VERSION 5.8 ;
BUSBITCHARS "[]" ;
DIVIDERCHAR "/" ;
UNITS
    DATABASE MICRONS 1000 ;
END UNITS

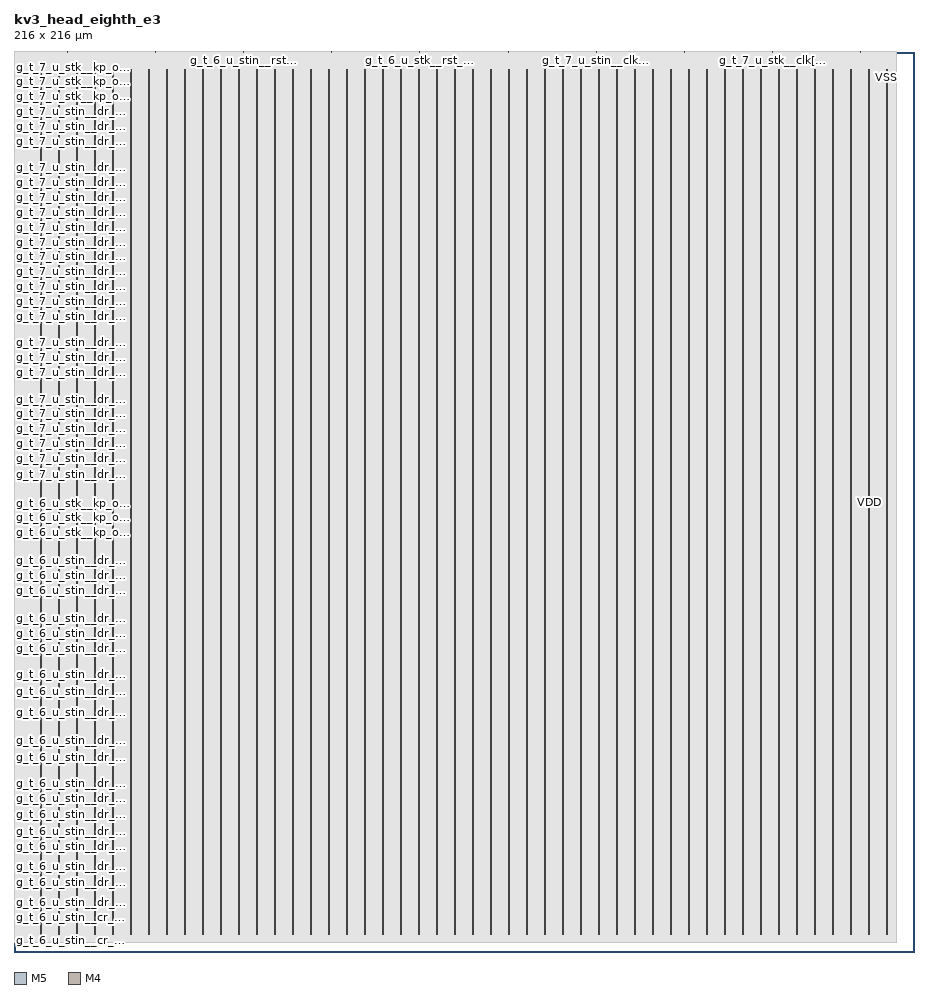
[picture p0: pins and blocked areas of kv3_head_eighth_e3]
MACRO kv3_head_eighth_e3
  FOREIGN kv3_head_eighth_e3 0 0 ;
  CLASS BLOCK ;
  SIZE 216 BY 216 ;
  PIN g_t_6_u_l8__clk[0]
    DIRECTION INPUT ;
    USE SIGNAL ;
    PORT
      LAYER M5 ;
        RECT  12.732 215.808 12.756 216 ;
    END
  END g_t_6_u_l8__clk[0]
  PIN g_t_6_u_stin__clk[0]
    DIRECTION INPUT ;
    USE SIGNAL ;
    PORT
      LAYER M5 ;
        RECT  33.9 215.808 33.924 216 ;
    END
  END g_t_6_u_stin__clk[0]
  PIN g_t_6_u_stin__cr_i[0]
    DIRECTION INPUT ;
    USE SIGNAL ;
    PORT
      LAYER M4 ;
        RECT  0 2.364 0.192 2.388 ;
    END
  END g_t_6_u_stin__cr_i[0]
  PIN g_t_6_u_stin__cr_i[10]
    DIRECTION INPUT ;
    USE SIGNAL ;
    PORT
      LAYER M4 ;
        RECT  0 6.3 0.192 6.324 ;
    END
  END g_t_6_u_stin__cr_i[10]
  PIN g_t_6_u_stin__cr_i[11]
    DIRECTION INPUT ;
    USE SIGNAL ;
    PORT
      LAYER M4 ;
        RECT  0 6.684 0.192 6.708 ;
    END
  END g_t_6_u_stin__cr_i[11]
  PIN g_t_6_u_stin__cr_i[12]
    DIRECTION INPUT ;
    USE SIGNAL ;
    PORT
      LAYER M4 ;
        RECT  0 7.116 0.192 7.14 ;
    END
  END g_t_6_u_stin__cr_i[12]
  PIN g_t_6_u_stin__cr_i[13]
    DIRECTION INPUT ;
    USE SIGNAL ;
    PORT
      LAYER M4 ;
        RECT  0 7.5 0.192 7.524 ;
    END
  END g_t_6_u_stin__cr_i[13]
  PIN g_t_6_u_stin__cr_i[14]
    DIRECTION INPUT ;
    USE SIGNAL ;
    PORT
      LAYER M4 ;
        RECT  0 7.884 0.192 7.908 ;
    END
  END g_t_6_u_stin__cr_i[14]
  PIN g_t_6_u_stin__cr_i[15]
    DIRECTION INPUT ;
    USE SIGNAL ;
    PORT
      LAYER M4 ;
        RECT  0 8.316 0.192 8.34 ;
    END
  END g_t_6_u_stin__cr_i[15]
  PIN g_t_6_u_stin__cr_i[1]
    DIRECTION INPUT ;
    USE SIGNAL ;
    PORT
      LAYER M4 ;
        RECT  0 2.748 0.192 2.772 ;
    END
  END g_t_6_u_stin__cr_i[1]
  PIN g_t_6_u_stin__cr_i[2]
    DIRECTION INPUT ;
    USE SIGNAL ;
    PORT
      LAYER M4 ;
        RECT  0 3.132 0.192 3.156 ;
    END
  END g_t_6_u_stin__cr_i[2]
  PIN g_t_6_u_stin__cr_i[3]
    DIRECTION INPUT ;
    USE SIGNAL ;
    PORT
      LAYER M4 ;
        RECT  0 3.516 0.192 3.54 ;
    END
  END g_t_6_u_stin__cr_i[3]
  PIN g_t_6_u_stin__cr_i[4]
    DIRECTION INPUT ;
    USE SIGNAL ;
    PORT
      LAYER M4 ;
        RECT  0 3.948 0.192 3.972 ;
    END
  END g_t_6_u_stin__cr_i[4]
  PIN g_t_6_u_stin__cr_i[5]
    DIRECTION INPUT ;
    USE SIGNAL ;
    PORT
      LAYER M4 ;
        RECT  0 4.332 0.192 4.356 ;
    END
  END g_t_6_u_stin__cr_i[5]
  PIN g_t_6_u_stin__cr_i[6]
    DIRECTION INPUT ;
    USE SIGNAL ;
    PORT
      LAYER M4 ;
        RECT  0 4.716 0.192 4.74 ;
    END
  END g_t_6_u_stin__cr_i[6]
  PIN g_t_6_u_stin__cr_i[7]
    DIRECTION INPUT ;
    USE SIGNAL ;
    PORT
      LAYER M4 ;
        RECT  0 5.1 0.192 5.124 ;
    END
  END g_t_6_u_stin__cr_i[7]
  PIN g_t_6_u_stin__cr_i[8]
    DIRECTION INPUT ;
    USE SIGNAL ;
    PORT
      LAYER M4 ;
        RECT  0 5.532 0.192 5.556 ;
    END
  END g_t_6_u_stin__cr_i[8]
  PIN g_t_6_u_stin__cr_i[9]
    DIRECTION INPUT ;
    USE SIGNAL ;
    PORT
      LAYER M4 ;
        RECT  0 5.916 0.192 5.94 ;
    END
  END g_t_6_u_stin__cr_i[9]
  PIN g_t_6_u_stin__dr_i[0]
    DIRECTION INPUT ;
    USE SIGNAL ;
    PORT
      LAYER M4 ;
        RECT  0 8.7 0.192 8.724 ;
    END
  END g_t_6_u_stin__dr_i[0]
  PIN g_t_6_u_stin__dr_i[100]
    DIRECTION INPUT ;
    USE SIGNAL ;
    PORT
      LAYER M4 ;
        RECT  0 48.348 0.192 48.372 ;
    END
  END g_t_6_u_stin__dr_i[100]
  PIN g_t_6_u_stin__dr_i[101]
    DIRECTION INPUT ;
    USE SIGNAL ;
    PORT
      LAYER M4 ;
        RECT  0 48.732 0.192 48.756 ;
    END
  END g_t_6_u_stin__dr_i[101]
  PIN g_t_6_u_stin__dr_i[102]
    DIRECTION INPUT ;
    USE SIGNAL ;
    PORT
      LAYER M4 ;
        RECT  0 49.116 0.192 49.14 ;
    END
  END g_t_6_u_stin__dr_i[102]
  PIN g_t_6_u_stin__dr_i[103]
    DIRECTION INPUT ;
    USE SIGNAL ;
    PORT
      LAYER M4 ;
        RECT  0 49.5 0.192 49.524 ;
    END
  END g_t_6_u_stin__dr_i[103]
  PIN g_t_6_u_stin__dr_i[104]
    DIRECTION INPUT ;
    USE SIGNAL ;
    PORT
      LAYER M4 ;
        RECT  0 49.932 0.192 49.956 ;
    END
  END g_t_6_u_stin__dr_i[104]
  PIN g_t_6_u_stin__dr_i[105]
    DIRECTION INPUT ;
    USE SIGNAL ;
    PORT
      LAYER M4 ;
        RECT  0 50.316 0.192 50.34 ;
    END
  END g_t_6_u_stin__dr_i[105]
  PIN g_t_6_u_stin__dr_i[106]
    DIRECTION INPUT ;
    USE SIGNAL ;
    PORT
      LAYER M4 ;
        RECT  0 50.7 0.192 50.724 ;
    END
  END g_t_6_u_stin__dr_i[106]
  PIN g_t_6_u_stin__dr_i[107]
    DIRECTION INPUT ;
    USE SIGNAL ;
    PORT
      LAYER M4 ;
        RECT  0 51.084 0.192 51.108 ;
    END
  END g_t_6_u_stin__dr_i[107]
  PIN g_t_6_u_stin__dr_i[108]
    DIRECTION INPUT ;
    USE SIGNAL ;
    PORT
      LAYER M4 ;
        RECT  0 51.516 0.192 51.54 ;
    END
  END g_t_6_u_stin__dr_i[108]
  PIN g_t_6_u_stin__dr_i[109]
    DIRECTION INPUT ;
    USE SIGNAL ;
    PORT
      LAYER M4 ;
        RECT  0 51.9 0.192 51.924 ;
    END
  END g_t_6_u_stin__dr_i[109]
  PIN g_t_6_u_stin__dr_i[10]
    DIRECTION INPUT ;
    USE SIGNAL ;
    PORT
      LAYER M4 ;
        RECT  0 12.636 0.192 12.66 ;
    END
  END g_t_6_u_stin__dr_i[10]
  PIN g_t_6_u_stin__dr_i[110]
    DIRECTION INPUT ;
    USE SIGNAL ;
    PORT
      LAYER M4 ;
        RECT  0 52.284 0.192 52.308 ;
    END
  END g_t_6_u_stin__dr_i[110]
  PIN g_t_6_u_stin__dr_i[111]
    DIRECTION INPUT ;
    USE SIGNAL ;
    PORT
      LAYER M4 ;
        RECT  0 52.668 0.192 52.692 ;
    END
  END g_t_6_u_stin__dr_i[111]
  PIN g_t_6_u_stin__dr_i[112]
    DIRECTION INPUT ;
    USE SIGNAL ;
    PORT
      LAYER M4 ;
        RECT  0 53.1 0.192 53.124 ;
    END
  END g_t_6_u_stin__dr_i[112]
  PIN g_t_6_u_stin__dr_i[113]
    DIRECTION INPUT ;
    USE SIGNAL ;
    PORT
      LAYER M4 ;
        RECT  0 53.484 0.192 53.508 ;
    END
  END g_t_6_u_stin__dr_i[113]
  PIN g_t_6_u_stin__dr_i[114]
    DIRECTION INPUT ;
    USE SIGNAL ;
    PORT
      LAYER M4 ;
        RECT  0 53.868 0.192 53.892 ;
    END
  END g_t_6_u_stin__dr_i[114]
  PIN g_t_6_u_stin__dr_i[115]
    DIRECTION INPUT ;
    USE SIGNAL ;
    PORT
      LAYER M4 ;
        RECT  0 54.252 0.192 54.276 ;
    END
  END g_t_6_u_stin__dr_i[115]
  PIN g_t_6_u_stin__dr_i[116]
    DIRECTION INPUT ;
    USE SIGNAL ;
    PORT
      LAYER M4 ;
        RECT  0 54.684 0.192 54.708 ;
    END
  END g_t_6_u_stin__dr_i[116]
  PIN g_t_6_u_stin__dr_i[117]
    DIRECTION INPUT ;
    USE SIGNAL ;
    PORT
      LAYER M4 ;
        RECT  0 55.068 0.192 55.092 ;
    END
  END g_t_6_u_stin__dr_i[117]
  PIN g_t_6_u_stin__dr_i[118]
    DIRECTION INPUT ;
    USE SIGNAL ;
    PORT
      LAYER M4 ;
        RECT  0 55.452 0.192 55.476 ;
    END
  END g_t_6_u_stin__dr_i[118]
  PIN g_t_6_u_stin__dr_i[119]
    DIRECTION INPUT ;
    USE SIGNAL ;
    PORT
      LAYER M4 ;
        RECT  0 55.884 0.192 55.908 ;
    END
  END g_t_6_u_stin__dr_i[119]
  PIN g_t_6_u_stin__dr_i[11]
    DIRECTION INPUT ;
    USE SIGNAL ;
    PORT
      LAYER M4 ;
        RECT  0 13.068 0.192 13.092 ;
    END
  END g_t_6_u_stin__dr_i[11]
  PIN g_t_6_u_stin__dr_i[120]
    DIRECTION INPUT ;
    USE SIGNAL ;
    PORT
      LAYER M4 ;
        RECT  0 56.268 0.192 56.292 ;
    END
  END g_t_6_u_stin__dr_i[120]
  PIN g_t_6_u_stin__dr_i[121]
    DIRECTION INPUT ;
    USE SIGNAL ;
    PORT
      LAYER M4 ;
        RECT  0 56.652 0.192 56.676 ;
    END
  END g_t_6_u_stin__dr_i[121]
  PIN g_t_6_u_stin__dr_i[122]
    DIRECTION INPUT ;
    USE SIGNAL ;
    PORT
      LAYER M4 ;
        RECT  0 57.036 0.192 57.06 ;
    END
  END g_t_6_u_stin__dr_i[122]
  PIN g_t_6_u_stin__dr_i[123]
    DIRECTION INPUT ;
    USE SIGNAL ;
    PORT
      LAYER M4 ;
        RECT  0 57.468 0.192 57.492 ;
    END
  END g_t_6_u_stin__dr_i[123]
  PIN g_t_6_u_stin__dr_i[124]
    DIRECTION INPUT ;
    USE SIGNAL ;
    PORT
      LAYER M4 ;
        RECT  0 57.852 0.192 57.876 ;
    END
  END g_t_6_u_stin__dr_i[124]
  PIN g_t_6_u_stin__dr_i[125]
    DIRECTION INPUT ;
    USE SIGNAL ;
    PORT
      LAYER M4 ;
        RECT  0 58.236 0.192 58.26 ;
    END
  END g_t_6_u_stin__dr_i[125]
  PIN g_t_6_u_stin__dr_i[126]
    DIRECTION INPUT ;
    USE SIGNAL ;
    PORT
      LAYER M4 ;
        RECT  0 58.62 0.192 58.644 ;
    END
  END g_t_6_u_stin__dr_i[126]
  PIN g_t_6_u_stin__dr_i[127]
    DIRECTION INPUT ;
    USE SIGNAL ;
    PORT
      LAYER M4 ;
        RECT  0 59.052 0.192 59.076 ;
    END
  END g_t_6_u_stin__dr_i[127]
  PIN g_t_6_u_stin__dr_i[128]
    DIRECTION INPUT ;
    USE SIGNAL ;
    PORT
      LAYER M4 ;
        RECT  0 59.436 0.192 59.46 ;
    END
  END g_t_6_u_stin__dr_i[128]
  PIN g_t_6_u_stin__dr_i[129]
    DIRECTION INPUT ;
    USE SIGNAL ;
    PORT
      LAYER M4 ;
        RECT  0 59.82 0.192 59.844 ;
    END
  END g_t_6_u_stin__dr_i[129]
  PIN g_t_6_u_stin__dr_i[12]
    DIRECTION INPUT ;
    USE SIGNAL ;
    PORT
      LAYER M4 ;
        RECT  0 13.452 0.192 13.476 ;
    END
  END g_t_6_u_stin__dr_i[12]
  PIN g_t_6_u_stin__dr_i[130]
    DIRECTION INPUT ;
    USE SIGNAL ;
    PORT
      LAYER M4 ;
        RECT  0 60.204 0.192 60.228 ;
    END
  END g_t_6_u_stin__dr_i[130]
  PIN g_t_6_u_stin__dr_i[131]
    DIRECTION INPUT ;
    USE SIGNAL ;
    PORT
      LAYER M4 ;
        RECT  0 60.636 0.192 60.66 ;
    END
  END g_t_6_u_stin__dr_i[131]
  PIN g_t_6_u_stin__dr_i[132]
    DIRECTION INPUT ;
    USE SIGNAL ;
    PORT
      LAYER M4 ;
        RECT  0 61.02 0.192 61.044 ;
    END
  END g_t_6_u_stin__dr_i[132]
  PIN g_t_6_u_stin__dr_i[133]
    DIRECTION INPUT ;
    USE SIGNAL ;
    PORT
      LAYER M4 ;
        RECT  0 61.404 0.192 61.428 ;
    END
  END g_t_6_u_stin__dr_i[133]
  PIN g_t_6_u_stin__dr_i[134]
    DIRECTION INPUT ;
    USE SIGNAL ;
    PORT
      LAYER M4 ;
        RECT  0 61.788 0.192 61.812 ;
    END
  END g_t_6_u_stin__dr_i[134]
  PIN g_t_6_u_stin__dr_i[135]
    DIRECTION INPUT ;
    USE SIGNAL ;
    PORT
      LAYER M4 ;
        RECT  0 62.22 0.192 62.244 ;
    END
  END g_t_6_u_stin__dr_i[135]
  PIN g_t_6_u_stin__dr_i[136]
    DIRECTION INPUT ;
    USE SIGNAL ;
    PORT
      LAYER M4 ;
        RECT  0 62.604 0.192 62.628 ;
    END
  END g_t_6_u_stin__dr_i[136]
  PIN g_t_6_u_stin__dr_i[137]
    DIRECTION INPUT ;
    USE SIGNAL ;
    PORT
      LAYER M4 ;
        RECT  0 62.988 0.192 63.012 ;
    END
  END g_t_6_u_stin__dr_i[137]
  PIN g_t_6_u_stin__dr_i[138]
    DIRECTION INPUT ;
    USE SIGNAL ;
    PORT
      LAYER M4 ;
        RECT  0 63.372 0.192 63.396 ;
    END
  END g_t_6_u_stin__dr_i[138]
  PIN g_t_6_u_stin__dr_i[139]
    DIRECTION INPUT ;
    USE SIGNAL ;
    PORT
      LAYER M4 ;
        RECT  0 63.804 0.192 63.828 ;
    END
  END g_t_6_u_stin__dr_i[139]
  PIN g_t_6_u_stin__dr_i[13]
    DIRECTION INPUT ;
    USE SIGNAL ;
    PORT
      LAYER M4 ;
        RECT  0 13.836 0.192 13.86 ;
    END
  END g_t_6_u_stin__dr_i[13]
  PIN g_t_6_u_stin__dr_i[140]
    DIRECTION INPUT ;
    USE SIGNAL ;
    PORT
      LAYER M4 ;
        RECT  0 64.188 0.192 64.212 ;
    END
  END g_t_6_u_stin__dr_i[140]
  PIN g_t_6_u_stin__dr_i[141]
    DIRECTION INPUT ;
    USE SIGNAL ;
    PORT
      LAYER M4 ;
        RECT  0 64.572 0.192 64.596 ;
    END
  END g_t_6_u_stin__dr_i[141]
  PIN g_t_6_u_stin__dr_i[142]
    DIRECTION INPUT ;
    USE SIGNAL ;
    PORT
      LAYER M4 ;
        RECT  0 64.956 0.192 64.98 ;
    END
  END g_t_6_u_stin__dr_i[142]
  PIN g_t_6_u_stin__dr_i[143]
    DIRECTION INPUT ;
    USE SIGNAL ;
    PORT
      LAYER M4 ;
        RECT  0 65.388 0.192 65.412 ;
    END
  END g_t_6_u_stin__dr_i[143]
  PIN g_t_6_u_stin__dr_i[144]
    DIRECTION INPUT ;
    USE SIGNAL ;
    PORT
      LAYER M4 ;
        RECT  0 65.772 0.192 65.796 ;
    END
  END g_t_6_u_stin__dr_i[144]
  PIN g_t_6_u_stin__dr_i[145]
    DIRECTION INPUT ;
    USE SIGNAL ;
    PORT
      LAYER M4 ;
        RECT  0 66.156 0.192 66.18 ;
    END
  END g_t_6_u_stin__dr_i[145]
  PIN g_t_6_u_stin__dr_i[146]
    DIRECTION INPUT ;
    USE SIGNAL ;
    PORT
      LAYER M4 ;
        RECT  0 66.54 0.192 66.564 ;
    END
  END g_t_6_u_stin__dr_i[146]
  PIN g_t_6_u_stin__dr_i[147]
    DIRECTION INPUT ;
    USE SIGNAL ;
    PORT
      LAYER M4 ;
        RECT  0 66.972 0.192 66.996 ;
    END
  END g_t_6_u_stin__dr_i[147]
  PIN g_t_6_u_stin__dr_i[148]
    DIRECTION INPUT ;
    USE SIGNAL ;
    PORT
      LAYER M4 ;
        RECT  0 67.356 0.192 67.38 ;
    END
  END g_t_6_u_stin__dr_i[148]
  PIN g_t_6_u_stin__dr_i[149]
    DIRECTION INPUT ;
    USE SIGNAL ;
    PORT
      LAYER M4 ;
        RECT  0 67.74 0.192 67.764 ;
    END
  END g_t_6_u_stin__dr_i[149]
  PIN g_t_6_u_stin__dr_i[14]
    DIRECTION INPUT ;
    USE SIGNAL ;
    PORT
      LAYER M4 ;
        RECT  0 14.22 0.192 14.244 ;
    END
  END g_t_6_u_stin__dr_i[14]
  PIN g_t_6_u_stin__dr_i[150]
    DIRECTION INPUT ;
    USE SIGNAL ;
    PORT
      LAYER M4 ;
        RECT  0 68.172 0.192 68.196 ;
    END
  END g_t_6_u_stin__dr_i[150]
  PIN g_t_6_u_stin__dr_i[151]
    DIRECTION INPUT ;
    USE SIGNAL ;
    PORT
      LAYER M4 ;
        RECT  0 68.556 0.192 68.58 ;
    END
  END g_t_6_u_stin__dr_i[151]
  PIN g_t_6_u_stin__dr_i[152]
    DIRECTION INPUT ;
    USE SIGNAL ;
    PORT
      LAYER M4 ;
        RECT  0 68.94 0.192 68.964 ;
    END
  END g_t_6_u_stin__dr_i[152]
  PIN g_t_6_u_stin__dr_i[153]
    DIRECTION INPUT ;
    USE SIGNAL ;
    PORT
      LAYER M4 ;
        RECT  0 69.324 0.192 69.348 ;
    END
  END g_t_6_u_stin__dr_i[153]
  PIN g_t_6_u_stin__dr_i[154]
    DIRECTION INPUT ;
    USE SIGNAL ;
    PORT
      LAYER M4 ;
        RECT  0 69.756 0.192 69.78 ;
    END
  END g_t_6_u_stin__dr_i[154]
  PIN g_t_6_u_stin__dr_i[155]
    DIRECTION INPUT ;
    USE SIGNAL ;
    PORT
      LAYER M4 ;
        RECT  0 70.14 0.192 70.164 ;
    END
  END g_t_6_u_stin__dr_i[155]
  PIN g_t_6_u_stin__dr_i[156]
    DIRECTION INPUT ;
    USE SIGNAL ;
    PORT
      LAYER M4 ;
        RECT  0 70.524 0.192 70.548 ;
    END
  END g_t_6_u_stin__dr_i[156]
  PIN g_t_6_u_stin__dr_i[157]
    DIRECTION INPUT ;
    USE SIGNAL ;
    PORT
      LAYER M4 ;
        RECT  0 70.908 0.192 70.932 ;
    END
  END g_t_6_u_stin__dr_i[157]
  PIN g_t_6_u_stin__dr_i[158]
    DIRECTION INPUT ;
    USE SIGNAL ;
    PORT
      LAYER M4 ;
        RECT  0 71.34 0.192 71.364 ;
    END
  END g_t_6_u_stin__dr_i[158]
  PIN g_t_6_u_stin__dr_i[159]
    DIRECTION INPUT ;
    USE SIGNAL ;
    PORT
      LAYER M4 ;
        RECT  0 71.724 0.192 71.748 ;
    END
  END g_t_6_u_stin__dr_i[159]
  PIN g_t_6_u_stin__dr_i[15]
    DIRECTION INPUT ;
    USE SIGNAL ;
    PORT
      LAYER M4 ;
        RECT  0 14.652 0.192 14.676 ;
    END
  END g_t_6_u_stin__dr_i[15]
  PIN g_t_6_u_stin__dr_i[160]
    DIRECTION INPUT ;
    USE SIGNAL ;
    PORT
      LAYER M4 ;
        RECT  0 72.108 0.192 72.132 ;
    END
  END g_t_6_u_stin__dr_i[160]
  PIN g_t_6_u_stin__dr_i[161]
    DIRECTION INPUT ;
    USE SIGNAL ;
    PORT
      LAYER M4 ;
        RECT  0 72.492 0.192 72.516 ;
    END
  END g_t_6_u_stin__dr_i[161]
  PIN g_t_6_u_stin__dr_i[162]
    DIRECTION INPUT ;
    USE SIGNAL ;
    PORT
      LAYER M4 ;
        RECT  0 72.924 0.192 72.948 ;
    END
  END g_t_6_u_stin__dr_i[162]
  PIN g_t_6_u_stin__dr_i[163]
    DIRECTION INPUT ;
    USE SIGNAL ;
    PORT
      LAYER M4 ;
        RECT  0 73.308 0.192 73.332 ;
    END
  END g_t_6_u_stin__dr_i[163]
  PIN g_t_6_u_stin__dr_i[164]
    DIRECTION INPUT ;
    USE SIGNAL ;
    PORT
      LAYER M4 ;
        RECT  0 73.692 0.192 73.716 ;
    END
  END g_t_6_u_stin__dr_i[164]
  PIN g_t_6_u_stin__dr_i[165]
    DIRECTION INPUT ;
    USE SIGNAL ;
    PORT
      LAYER M4 ;
        RECT  0 74.076 0.192 74.1 ;
    END
  END g_t_6_u_stin__dr_i[165]
  PIN g_t_6_u_stin__dr_i[166]
    DIRECTION INPUT ;
    USE SIGNAL ;
    PORT
      LAYER M4 ;
        RECT  0 74.508 0.192 74.532 ;
    END
  END g_t_6_u_stin__dr_i[166]
  PIN g_t_6_u_stin__dr_i[167]
    DIRECTION INPUT ;
    USE SIGNAL ;
    PORT
      LAYER M4 ;
        RECT  0 74.892 0.192 74.916 ;
    END
  END g_t_6_u_stin__dr_i[167]
  PIN g_t_6_u_stin__dr_i[168]
    DIRECTION INPUT ;
    USE SIGNAL ;
    PORT
      LAYER M4 ;
        RECT  0 75.276 0.192 75.3 ;
    END
  END g_t_6_u_stin__dr_i[168]
  PIN g_t_6_u_stin__dr_i[169]
    DIRECTION INPUT ;
    USE SIGNAL ;
    PORT
      LAYER M4 ;
        RECT  0 75.66 0.192 75.684 ;
    END
  END g_t_6_u_stin__dr_i[169]
  PIN g_t_6_u_stin__dr_i[16]
    DIRECTION INPUT ;
    USE SIGNAL ;
    PORT
      LAYER M4 ;
        RECT  0 15.036 0.192 15.06 ;
    END
  END g_t_6_u_stin__dr_i[16]
  PIN g_t_6_u_stin__dr_i[170]
    DIRECTION INPUT ;
    USE SIGNAL ;
    PORT
      LAYER M4 ;
        RECT  0 76.092 0.192 76.116 ;
    END
  END g_t_6_u_stin__dr_i[170]
  PIN g_t_6_u_stin__dr_i[171]
    DIRECTION INPUT ;
    USE SIGNAL ;
    PORT
      LAYER M4 ;
        RECT  0 76.476 0.192 76.5 ;
    END
  END g_t_6_u_stin__dr_i[171]
  PIN g_t_6_u_stin__dr_i[172]
    DIRECTION INPUT ;
    USE SIGNAL ;
    PORT
      LAYER M4 ;
        RECT  0 76.86 0.192 76.884 ;
    END
  END g_t_6_u_stin__dr_i[172]
  PIN g_t_6_u_stin__dr_i[173]
    DIRECTION INPUT ;
    USE SIGNAL ;
    PORT
      LAYER M4 ;
        RECT  0 77.244 0.192 77.268 ;
    END
  END g_t_6_u_stin__dr_i[173]
  PIN g_t_6_u_stin__dr_i[174]
    DIRECTION INPUT ;
    USE SIGNAL ;
    PORT
      LAYER M4 ;
        RECT  0 77.676 0.192 77.7 ;
    END
  END g_t_6_u_stin__dr_i[174]
  PIN g_t_6_u_stin__dr_i[175]
    DIRECTION INPUT ;
    USE SIGNAL ;
    PORT
      LAYER M4 ;
        RECT  0 78.06 0.192 78.084 ;
    END
  END g_t_6_u_stin__dr_i[175]
  PIN g_t_6_u_stin__dr_i[176]
    DIRECTION INPUT ;
    USE SIGNAL ;
    PORT
      LAYER M4 ;
        RECT  0 78.444 0.192 78.468 ;
    END
  END g_t_6_u_stin__dr_i[176]
  PIN g_t_6_u_stin__dr_i[177]
    DIRECTION INPUT ;
    USE SIGNAL ;
    PORT
      LAYER M4 ;
        RECT  0 78.876 0.192 78.9 ;
    END
  END g_t_6_u_stin__dr_i[177]
  PIN g_t_6_u_stin__dr_i[178]
    DIRECTION INPUT ;
    USE SIGNAL ;
    PORT
      LAYER M4 ;
        RECT  0 79.26 0.192 79.284 ;
    END
  END g_t_6_u_stin__dr_i[178]
  PIN g_t_6_u_stin__dr_i[179]
    DIRECTION INPUT ;
    USE SIGNAL ;
    PORT
      LAYER M4 ;
        RECT  0 79.644 0.192 79.668 ;
    END
  END g_t_6_u_stin__dr_i[179]
  PIN g_t_6_u_stin__dr_i[17]
    DIRECTION INPUT ;
    USE SIGNAL ;
    PORT
      LAYER M4 ;
        RECT  0 15.42 0.192 15.444 ;
    END
  END g_t_6_u_stin__dr_i[17]
  PIN g_t_6_u_stin__dr_i[180]
    DIRECTION INPUT ;
    USE SIGNAL ;
    PORT
      LAYER M4 ;
        RECT  0 80.028 0.192 80.052 ;
    END
  END g_t_6_u_stin__dr_i[180]
  PIN g_t_6_u_stin__dr_i[181]
    DIRECTION INPUT ;
    USE SIGNAL ;
    PORT
      LAYER M4 ;
        RECT  0 80.46 0.192 80.484 ;
    END
  END g_t_6_u_stin__dr_i[181]
  PIN g_t_6_u_stin__dr_i[182]
    DIRECTION INPUT ;
    USE SIGNAL ;
    PORT
      LAYER M4 ;
        RECT  0 80.844 0.192 80.868 ;
    END
  END g_t_6_u_stin__dr_i[182]
  PIN g_t_6_u_stin__dr_i[183]
    DIRECTION INPUT ;
    USE SIGNAL ;
    PORT
      LAYER M4 ;
        RECT  0 81.228 0.192 81.252 ;
    END
  END g_t_6_u_stin__dr_i[183]
  PIN g_t_6_u_stin__dr_i[184]
    DIRECTION INPUT ;
    USE SIGNAL ;
    PORT
      LAYER M4 ;
        RECT  0 81.612 0.192 81.636 ;
    END
  END g_t_6_u_stin__dr_i[184]
  PIN g_t_6_u_stin__dr_i[185]
    DIRECTION INPUT ;
    USE SIGNAL ;
    PORT
      LAYER M4 ;
        RECT  0 82.044 0.192 82.068 ;
    END
  END g_t_6_u_stin__dr_i[185]
  PIN g_t_6_u_stin__dr_i[186]
    DIRECTION INPUT ;
    USE SIGNAL ;
    PORT
      LAYER M4 ;
        RECT  0 82.428 0.192 82.452 ;
    END
  END g_t_6_u_stin__dr_i[186]
  PIN g_t_6_u_stin__dr_i[187]
    DIRECTION INPUT ;
    USE SIGNAL ;
    PORT
      LAYER M4 ;
        RECT  0 82.812 0.192 82.836 ;
    END
  END g_t_6_u_stin__dr_i[187]
  PIN g_t_6_u_stin__dr_i[188]
    DIRECTION INPUT ;
    USE SIGNAL ;
    PORT
      LAYER M4 ;
        RECT  0 83.196 0.192 83.22 ;
    END
  END g_t_6_u_stin__dr_i[188]
  PIN g_t_6_u_stin__dr_i[189]
    DIRECTION INPUT ;
    USE SIGNAL ;
    PORT
      LAYER M4 ;
        RECT  0 83.628 0.192 83.652 ;
    END
  END g_t_6_u_stin__dr_i[189]
  PIN g_t_6_u_stin__dr_i[18]
    DIRECTION INPUT ;
    USE SIGNAL ;
    PORT
      LAYER M4 ;
        RECT  0 15.804 0.192 15.828 ;
    END
  END g_t_6_u_stin__dr_i[18]
  PIN g_t_6_u_stin__dr_i[190]
    DIRECTION INPUT ;
    USE SIGNAL ;
    PORT
      LAYER M4 ;
        RECT  0 84.012 0.192 84.036 ;
    END
  END g_t_6_u_stin__dr_i[190]
  PIN g_t_6_u_stin__dr_i[191]
    DIRECTION INPUT ;
    USE SIGNAL ;
    PORT
      LAYER M4 ;
        RECT  0 84.396 0.192 84.42 ;
    END
  END g_t_6_u_stin__dr_i[191]
  PIN g_t_6_u_stin__dr_i[192]
    DIRECTION INPUT ;
    USE SIGNAL ;
    PORT
      LAYER M4 ;
        RECT  0 84.78 0.192 84.804 ;
    END
  END g_t_6_u_stin__dr_i[192]
  PIN g_t_6_u_stin__dr_i[193]
    DIRECTION INPUT ;
    USE SIGNAL ;
    PORT
      LAYER M4 ;
        RECT  0 85.212 0.192 85.236 ;
    END
  END g_t_6_u_stin__dr_i[193]
  PIN g_t_6_u_stin__dr_i[194]
    DIRECTION INPUT ;
    USE SIGNAL ;
    PORT
      LAYER M4 ;
        RECT  0 85.596 0.192 85.62 ;
    END
  END g_t_6_u_stin__dr_i[194]
  PIN g_t_6_u_stin__dr_i[195]
    DIRECTION INPUT ;
    USE SIGNAL ;
    PORT
      LAYER M4 ;
        RECT  0 85.98 0.192 86.004 ;
    END
  END g_t_6_u_stin__dr_i[195]
  PIN g_t_6_u_stin__dr_i[196]
    DIRECTION INPUT ;
    USE SIGNAL ;
    PORT
      LAYER M4 ;
        RECT  0 86.364 0.192 86.388 ;
    END
  END g_t_6_u_stin__dr_i[196]
  PIN g_t_6_u_stin__dr_i[197]
    DIRECTION INPUT ;
    USE SIGNAL ;
    PORT
      LAYER M4 ;
        RECT  0 86.796 0.192 86.82 ;
    END
  END g_t_6_u_stin__dr_i[197]
  PIN g_t_6_u_stin__dr_i[198]
    DIRECTION INPUT ;
    USE SIGNAL ;
    PORT
      LAYER M4 ;
        RECT  0 87.18 0.192 87.204 ;
    END
  END g_t_6_u_stin__dr_i[198]
  PIN g_t_6_u_stin__dr_i[199]
    DIRECTION INPUT ;
    USE SIGNAL ;
    PORT
      LAYER M4 ;
        RECT  0 87.564 0.192 87.588 ;
    END
  END g_t_6_u_stin__dr_i[199]
  PIN g_t_6_u_stin__dr_i[19]
    DIRECTION INPUT ;
    USE SIGNAL ;
    PORT
      LAYER M4 ;
        RECT  0 16.236 0.192 16.26 ;
    END
  END g_t_6_u_stin__dr_i[19]
  PIN g_t_6_u_stin__dr_i[1]
    DIRECTION INPUT ;
    USE SIGNAL ;
    PORT
      LAYER M4 ;
        RECT  0 9.084 0.192 9.108 ;
    END
  END g_t_6_u_stin__dr_i[1]
  PIN g_t_6_u_stin__dr_i[200]
    DIRECTION INPUT ;
    USE SIGNAL ;
    PORT
      LAYER M4 ;
        RECT  0 87.948 0.192 87.972 ;
    END
  END g_t_6_u_stin__dr_i[200]
  PIN g_t_6_u_stin__dr_i[201]
    DIRECTION INPUT ;
    USE SIGNAL ;
    PORT
      LAYER M4 ;
        RECT  0 88.38 0.192 88.404 ;
    END
  END g_t_6_u_stin__dr_i[201]
  PIN g_t_6_u_stin__dr_i[202]
    DIRECTION INPUT ;
    USE SIGNAL ;
    PORT
      LAYER M4 ;
        RECT  0 88.764 0.192 88.788 ;
    END
  END g_t_6_u_stin__dr_i[202]
  PIN g_t_6_u_stin__dr_i[203]
    DIRECTION INPUT ;
    USE SIGNAL ;
    PORT
      LAYER M4 ;
        RECT  0 89.148 0.192 89.172 ;
    END
  END g_t_6_u_stin__dr_i[203]
  PIN g_t_6_u_stin__dr_i[204]
    DIRECTION INPUT ;
    USE SIGNAL ;
    PORT
      LAYER M4 ;
        RECT  0 89.532 0.192 89.556 ;
    END
  END g_t_6_u_stin__dr_i[204]
  PIN g_t_6_u_stin__dr_i[205]
    DIRECTION INPUT ;
    USE SIGNAL ;
    PORT
      LAYER M4 ;
        RECT  0 89.964 0.192 89.988 ;
    END
  END g_t_6_u_stin__dr_i[205]
  PIN g_t_6_u_stin__dr_i[206]
    DIRECTION INPUT ;
    USE SIGNAL ;
    PORT
      LAYER M4 ;
        RECT  0 90.348 0.192 90.372 ;
    END
  END g_t_6_u_stin__dr_i[206]
  PIN g_t_6_u_stin__dr_i[207]
    DIRECTION INPUT ;
    USE SIGNAL ;
    PORT
      LAYER M4 ;
        RECT  0 90.732 0.192 90.756 ;
    END
  END g_t_6_u_stin__dr_i[207]
  PIN g_t_6_u_stin__dr_i[208]
    DIRECTION INPUT ;
    USE SIGNAL ;
    PORT
      LAYER M4 ;
        RECT  0 91.164 0.192 91.188 ;
    END
  END g_t_6_u_stin__dr_i[208]
  PIN g_t_6_u_stin__dr_i[209]
    DIRECTION INPUT ;
    USE SIGNAL ;
    PORT
      LAYER M4 ;
        RECT  0 91.548 0.192 91.572 ;
    END
  END g_t_6_u_stin__dr_i[209]
  PIN g_t_6_u_stin__dr_i[20]
    DIRECTION INPUT ;
    USE SIGNAL ;
    PORT
      LAYER M4 ;
        RECT  0 16.62 0.192 16.644 ;
    END
  END g_t_6_u_stin__dr_i[20]
  PIN g_t_6_u_stin__dr_i[210]
    DIRECTION INPUT ;
    USE SIGNAL ;
    PORT
      LAYER M4 ;
        RECT  0 91.932 0.192 91.956 ;
    END
  END g_t_6_u_stin__dr_i[210]
  PIN g_t_6_u_stin__dr_i[211]
    DIRECTION INPUT ;
    USE SIGNAL ;
    PORT
      LAYER M4 ;
        RECT  0 92.316 0.192 92.34 ;
    END
  END g_t_6_u_stin__dr_i[211]
  PIN g_t_6_u_stin__dr_i[212]
    DIRECTION INPUT ;
    USE SIGNAL ;
    PORT
      LAYER M4 ;
        RECT  0 92.748 0.192 92.772 ;
    END
  END g_t_6_u_stin__dr_i[212]
  PIN g_t_6_u_stin__dr_i[213]
    DIRECTION INPUT ;
    USE SIGNAL ;
    PORT
      LAYER M4 ;
        RECT  0 93.132 0.192 93.156 ;
    END
  END g_t_6_u_stin__dr_i[213]
  PIN g_t_6_u_stin__dr_i[214]
    DIRECTION INPUT ;
    USE SIGNAL ;
    PORT
      LAYER M4 ;
        RECT  0 93.516 0.192 93.54 ;
    END
  END g_t_6_u_stin__dr_i[214]
  PIN g_t_6_u_stin__dr_i[215]
    DIRECTION INPUT ;
    USE SIGNAL ;
    PORT
      LAYER M4 ;
        RECT  0 93.9 0.192 93.924 ;
    END
  END g_t_6_u_stin__dr_i[215]
  PIN g_t_6_u_stin__dr_i[216]
    DIRECTION INPUT ;
    USE SIGNAL ;
    PORT
      LAYER M4 ;
        RECT  0 94.332 0.192 94.356 ;
    END
  END g_t_6_u_stin__dr_i[216]
  PIN g_t_6_u_stin__dr_i[21]
    DIRECTION INPUT ;
    USE SIGNAL ;
    PORT
      LAYER M4 ;
        RECT  0 17.004 0.192 17.028 ;
    END
  END g_t_6_u_stin__dr_i[21]
  PIN g_t_6_u_stin__dr_i[22]
    DIRECTION INPUT ;
    USE SIGNAL ;
    PORT
      LAYER M4 ;
        RECT  0 17.388 0.192 17.412 ;
    END
  END g_t_6_u_stin__dr_i[22]
  PIN g_t_6_u_stin__dr_i[23]
    DIRECTION INPUT ;
    USE SIGNAL ;
    PORT
      LAYER M4 ;
        RECT  0 17.82 0.192 17.844 ;
    END
  END g_t_6_u_stin__dr_i[23]
  PIN g_t_6_u_stin__dr_i[24]
    DIRECTION INPUT ;
    USE SIGNAL ;
    PORT
      LAYER M4 ;
        RECT  0 18.204 0.192 18.228 ;
    END
  END g_t_6_u_stin__dr_i[24]
  PIN g_t_6_u_stin__dr_i[25]
    DIRECTION INPUT ;
    USE SIGNAL ;
    PORT
      LAYER M4 ;
        RECT  0 18.588 0.192 18.612 ;
    END
  END g_t_6_u_stin__dr_i[25]
  PIN g_t_6_u_stin__dr_i[26]
    DIRECTION INPUT ;
    USE SIGNAL ;
    PORT
      LAYER M4 ;
        RECT  0 18.972 0.192 18.996 ;
    END
  END g_t_6_u_stin__dr_i[26]
  PIN g_t_6_u_stin__dr_i[27]
    DIRECTION INPUT ;
    USE SIGNAL ;
    PORT
      LAYER M4 ;
        RECT  0 19.404 0.192 19.428 ;
    END
  END g_t_6_u_stin__dr_i[27]
  PIN g_t_6_u_stin__dr_i[28]
    DIRECTION INPUT ;
    USE SIGNAL ;
    PORT
      LAYER M4 ;
        RECT  0 19.788 0.192 19.812 ;
    END
  END g_t_6_u_stin__dr_i[28]
  PIN g_t_6_u_stin__dr_i[29]
    DIRECTION INPUT ;
    USE SIGNAL ;
    PORT
      LAYER M4 ;
        RECT  0 20.172 0.192 20.196 ;
    END
  END g_t_6_u_stin__dr_i[29]
  PIN g_t_6_u_stin__dr_i[2]
    DIRECTION INPUT ;
    USE SIGNAL ;
    PORT
      LAYER M4 ;
        RECT  0 9.468 0.192 9.492 ;
    END
  END g_t_6_u_stin__dr_i[2]
  PIN g_t_6_u_stin__dr_i[30]
    DIRECTION INPUT ;
    USE SIGNAL ;
    PORT
      LAYER M4 ;
        RECT  0 20.604 0.192 20.628 ;
    END
  END g_t_6_u_stin__dr_i[30]
  PIN g_t_6_u_stin__dr_i[31]
    DIRECTION INPUT ;
    USE SIGNAL ;
    PORT
      LAYER M4 ;
        RECT  0 20.988 0.192 21.012 ;
    END
  END g_t_6_u_stin__dr_i[31]
  PIN g_t_6_u_stin__dr_i[32]
    DIRECTION INPUT ;
    USE SIGNAL ;
    PORT
      LAYER M4 ;
        RECT  0 21.372 0.192 21.396 ;
    END
  END g_t_6_u_stin__dr_i[32]
  PIN g_t_6_u_stin__dr_i[33]
    DIRECTION INPUT ;
    USE SIGNAL ;
    PORT
      LAYER M4 ;
        RECT  0 21.756 0.192 21.78 ;
    END
  END g_t_6_u_stin__dr_i[33]
  PIN g_t_6_u_stin__dr_i[34]
    DIRECTION INPUT ;
    USE SIGNAL ;
    PORT
      LAYER M4 ;
        RECT  0 22.188 0.192 22.212 ;
    END
  END g_t_6_u_stin__dr_i[34]
  PIN g_t_6_u_stin__dr_i[35]
    DIRECTION INPUT ;
    USE SIGNAL ;
    PORT
      LAYER M4 ;
        RECT  0 22.572 0.192 22.596 ;
    END
  END g_t_6_u_stin__dr_i[35]
  PIN g_t_6_u_stin__dr_i[36]
    DIRECTION INPUT ;
    USE SIGNAL ;
    PORT
      LAYER M4 ;
        RECT  0 22.956 0.192 22.98 ;
    END
  END g_t_6_u_stin__dr_i[36]
  PIN g_t_6_u_stin__dr_i[37]
    DIRECTION INPUT ;
    USE SIGNAL ;
    PORT
      LAYER M4 ;
        RECT  0 23.34 0.192 23.364 ;
    END
  END g_t_6_u_stin__dr_i[37]
  PIN g_t_6_u_stin__dr_i[38]
    DIRECTION INPUT ;
    USE SIGNAL ;
    PORT
      LAYER M4 ;
        RECT  0 23.772 0.192 23.796 ;
    END
  END g_t_6_u_stin__dr_i[38]
  PIN g_t_6_u_stin__dr_i[39]
    DIRECTION INPUT ;
    USE SIGNAL ;
    PORT
      LAYER M4 ;
        RECT  0 24.156 0.192 24.18 ;
    END
  END g_t_6_u_stin__dr_i[39]
  PIN g_t_6_u_stin__dr_i[3]
    DIRECTION INPUT ;
    USE SIGNAL ;
    PORT
      LAYER M4 ;
        RECT  0 9.9 0.192 9.924 ;
    END
  END g_t_6_u_stin__dr_i[3]
  PIN g_t_6_u_stin__dr_i[40]
    DIRECTION INPUT ;
    USE SIGNAL ;
    PORT
      LAYER M4 ;
        RECT  0 24.54 0.192 24.564 ;
    END
  END g_t_6_u_stin__dr_i[40]
  PIN g_t_6_u_stin__dr_i[41]
    DIRECTION INPUT ;
    USE SIGNAL ;
    PORT
      LAYER M4 ;
        RECT  0 24.924 0.192 24.948 ;
    END
  END g_t_6_u_stin__dr_i[41]
  PIN g_t_6_u_stin__dr_i[42]
    DIRECTION INPUT ;
    USE SIGNAL ;
    PORT
      LAYER M4 ;
        RECT  0 25.356 0.192 25.38 ;
    END
  END g_t_6_u_stin__dr_i[42]
  PIN g_t_6_u_stin__dr_i[43]
    DIRECTION INPUT ;
    USE SIGNAL ;
    PORT
      LAYER M4 ;
        RECT  0 25.74 0.192 25.764 ;
    END
  END g_t_6_u_stin__dr_i[43]
  PIN g_t_6_u_stin__dr_i[44]
    DIRECTION INPUT ;
    USE SIGNAL ;
    PORT
      LAYER M4 ;
        RECT  0 26.124 0.192 26.148 ;
    END
  END g_t_6_u_stin__dr_i[44]
  PIN g_t_6_u_stin__dr_i[45]
    DIRECTION INPUT ;
    USE SIGNAL ;
    PORT
      LAYER M4 ;
        RECT  0 26.508 0.192 26.532 ;
    END
  END g_t_6_u_stin__dr_i[45]
  PIN g_t_6_u_stin__dr_i[46]
    DIRECTION INPUT ;
    USE SIGNAL ;
    PORT
      LAYER M4 ;
        RECT  0 26.94 0.192 26.964 ;
    END
  END g_t_6_u_stin__dr_i[46]
  PIN g_t_6_u_stin__dr_i[47]
    DIRECTION INPUT ;
    USE SIGNAL ;
    PORT
      LAYER M4 ;
        RECT  0 27.324 0.192 27.348 ;
    END
  END g_t_6_u_stin__dr_i[47]
  PIN g_t_6_u_stin__dr_i[48]
    DIRECTION INPUT ;
    USE SIGNAL ;
    PORT
      LAYER M4 ;
        RECT  0 27.708 0.192 27.732 ;
    END
  END g_t_6_u_stin__dr_i[48]
  PIN g_t_6_u_stin__dr_i[49]
    DIRECTION INPUT ;
    USE SIGNAL ;
    PORT
      LAYER M4 ;
        RECT  0 28.092 0.192 28.116 ;
    END
  END g_t_6_u_stin__dr_i[49]
  PIN g_t_6_u_stin__dr_i[4]
    DIRECTION INPUT ;
    USE SIGNAL ;
    PORT
      LAYER M4 ;
        RECT  0 10.284 0.192 10.308 ;
    END
  END g_t_6_u_stin__dr_i[4]
  PIN g_t_6_u_stin__dr_i[50]
    DIRECTION INPUT ;
    USE SIGNAL ;
    PORT
      LAYER M4 ;
        RECT  0 28.524 0.192 28.548 ;
    END
  END g_t_6_u_stin__dr_i[50]
  PIN g_t_6_u_stin__dr_i[51]
    DIRECTION INPUT ;
    USE SIGNAL ;
    PORT
      LAYER M4 ;
        RECT  0 28.908 0.192 28.932 ;
    END
  END g_t_6_u_stin__dr_i[51]
  PIN g_t_6_u_stin__dr_i[52]
    DIRECTION INPUT ;
    USE SIGNAL ;
    PORT
      LAYER M4 ;
        RECT  0 29.292 0.192 29.316 ;
    END
  END g_t_6_u_stin__dr_i[52]
  PIN g_t_6_u_stin__dr_i[53]
    DIRECTION INPUT ;
    USE SIGNAL ;
    PORT
      LAYER M4 ;
        RECT  0 29.676 0.192 29.7 ;
    END
  END g_t_6_u_stin__dr_i[53]
  PIN g_t_6_u_stin__dr_i[54]
    DIRECTION INPUT ;
    USE SIGNAL ;
    PORT
      LAYER M4 ;
        RECT  0 30.108 0.192 30.132 ;
    END
  END g_t_6_u_stin__dr_i[54]
  PIN g_t_6_u_stin__dr_i[55]
    DIRECTION INPUT ;
    USE SIGNAL ;
    PORT
      LAYER M4 ;
        RECT  0 30.492 0.192 30.516 ;
    END
  END g_t_6_u_stin__dr_i[55]
  PIN g_t_6_u_stin__dr_i[56]
    DIRECTION INPUT ;
    USE SIGNAL ;
    PORT
      LAYER M4 ;
        RECT  0 30.876 0.192 30.9 ;
    END
  END g_t_6_u_stin__dr_i[56]
  PIN g_t_6_u_stin__dr_i[57]
    DIRECTION INPUT ;
    USE SIGNAL ;
    PORT
      LAYER M4 ;
        RECT  0 31.26 0.192 31.284 ;
    END
  END g_t_6_u_stin__dr_i[57]
  PIN g_t_6_u_stin__dr_i[58]
    DIRECTION INPUT ;
    USE SIGNAL ;
    PORT
      LAYER M4 ;
        RECT  0 31.692 0.192 31.716 ;
    END
  END g_t_6_u_stin__dr_i[58]
  PIN g_t_6_u_stin__dr_i[59]
    DIRECTION INPUT ;
    USE SIGNAL ;
    PORT
      LAYER M4 ;
        RECT  0 32.076 0.192 32.1 ;
    END
  END g_t_6_u_stin__dr_i[59]
  PIN g_t_6_u_stin__dr_i[5]
    DIRECTION INPUT ;
    USE SIGNAL ;
    PORT
      LAYER M4 ;
        RECT  0 10.668 0.192 10.692 ;
    END
  END g_t_6_u_stin__dr_i[5]
  PIN g_t_6_u_stin__dr_i[60]
    DIRECTION INPUT ;
    USE SIGNAL ;
    PORT
      LAYER M4 ;
        RECT  0 32.46 0.192 32.484 ;
    END
  END g_t_6_u_stin__dr_i[60]
  PIN g_t_6_u_stin__dr_i[61]
    DIRECTION INPUT ;
    USE SIGNAL ;
    PORT
      LAYER M4 ;
        RECT  0 32.892 0.192 32.916 ;
    END
  END g_t_6_u_stin__dr_i[61]
  PIN g_t_6_u_stin__dr_i[62]
    DIRECTION INPUT ;
    USE SIGNAL ;
    PORT
      LAYER M4 ;
        RECT  0 33.276 0.192 33.3 ;
    END
  END g_t_6_u_stin__dr_i[62]
  PIN g_t_6_u_stin__dr_i[63]
    DIRECTION INPUT ;
    USE SIGNAL ;
    PORT
      LAYER M4 ;
        RECT  0 33.66 0.192 33.684 ;
    END
  END g_t_6_u_stin__dr_i[63]
  PIN g_t_6_u_stin__dr_i[64]
    DIRECTION INPUT ;
    USE SIGNAL ;
    PORT
      LAYER M4 ;
        RECT  0 34.044 0.192 34.068 ;
    END
  END g_t_6_u_stin__dr_i[64]
  PIN g_t_6_u_stin__dr_i[65]
    DIRECTION INPUT ;
    USE SIGNAL ;
    PORT
      LAYER M4 ;
        RECT  0 34.476 0.192 34.5 ;
    END
  END g_t_6_u_stin__dr_i[65]
  PIN g_t_6_u_stin__dr_i[66]
    DIRECTION INPUT ;
    USE SIGNAL ;
    PORT
      LAYER M4 ;
        RECT  0 34.86 0.192 34.884 ;
    END
  END g_t_6_u_stin__dr_i[66]
  PIN g_t_6_u_stin__dr_i[67]
    DIRECTION INPUT ;
    USE SIGNAL ;
    PORT
      LAYER M4 ;
        RECT  0 35.244 0.192 35.268 ;
    END
  END g_t_6_u_stin__dr_i[67]
  PIN g_t_6_u_stin__dr_i[68]
    DIRECTION INPUT ;
    USE SIGNAL ;
    PORT
      LAYER M4 ;
        RECT  0 35.628 0.192 35.652 ;
    END
  END g_t_6_u_stin__dr_i[68]
  PIN g_t_6_u_stin__dr_i[69]
    DIRECTION INPUT ;
    USE SIGNAL ;
    PORT
      LAYER M4 ;
        RECT  0 36.06 0.192 36.084 ;
    END
  END g_t_6_u_stin__dr_i[69]
  PIN g_t_6_u_stin__dr_i[6]
    DIRECTION INPUT ;
    USE SIGNAL ;
    PORT
      LAYER M4 ;
        RECT  0 11.052 0.192 11.076 ;
    END
  END g_t_6_u_stin__dr_i[6]
  PIN g_t_6_u_stin__dr_i[70]
    DIRECTION INPUT ;
    USE SIGNAL ;
    PORT
      LAYER M4 ;
        RECT  0 36.444 0.192 36.468 ;
    END
  END g_t_6_u_stin__dr_i[70]
  PIN g_t_6_u_stin__dr_i[71]
    DIRECTION INPUT ;
    USE SIGNAL ;
    PORT
      LAYER M4 ;
        RECT  0 36.828 0.192 36.852 ;
    END
  END g_t_6_u_stin__dr_i[71]
  PIN g_t_6_u_stin__dr_i[72]
    DIRECTION INPUT ;
    USE SIGNAL ;
    PORT
      LAYER M4 ;
        RECT  0 37.212 0.192 37.236 ;
    END
  END g_t_6_u_stin__dr_i[72]
  PIN g_t_6_u_stin__dr_i[73]
    DIRECTION INPUT ;
    USE SIGNAL ;
    PORT
      LAYER M4 ;
        RECT  0 37.644 0.192 37.668 ;
    END
  END g_t_6_u_stin__dr_i[73]
  PIN g_t_6_u_stin__dr_i[74]
    DIRECTION INPUT ;
    USE SIGNAL ;
    PORT
      LAYER M4 ;
        RECT  0 38.028 0.192 38.052 ;
    END
  END g_t_6_u_stin__dr_i[74]
  PIN g_t_6_u_stin__dr_i[75]
    DIRECTION INPUT ;
    USE SIGNAL ;
    PORT
      LAYER M4 ;
        RECT  0 38.412 0.192 38.436 ;
    END
  END g_t_6_u_stin__dr_i[75]
  PIN g_t_6_u_stin__dr_i[76]
    DIRECTION INPUT ;
    USE SIGNAL ;
    PORT
      LAYER M4 ;
        RECT  0 38.796 0.192 38.82 ;
    END
  END g_t_6_u_stin__dr_i[76]
  PIN g_t_6_u_stin__dr_i[77]
    DIRECTION INPUT ;
    USE SIGNAL ;
    PORT
      LAYER M4 ;
        RECT  0 39.228 0.192 39.252 ;
    END
  END g_t_6_u_stin__dr_i[77]
  PIN g_t_6_u_stin__dr_i[78]
    DIRECTION INPUT ;
    USE SIGNAL ;
    PORT
      LAYER M4 ;
        RECT  0 39.612 0.192 39.636 ;
    END
  END g_t_6_u_stin__dr_i[78]
  PIN g_t_6_u_stin__dr_i[79]
    DIRECTION INPUT ;
    USE SIGNAL ;
    PORT
      LAYER M4 ;
        RECT  0 39.996 0.192 40.02 ;
    END
  END g_t_6_u_stin__dr_i[79]
  PIN g_t_6_u_stin__dr_i[7]
    DIRECTION INPUT ;
    USE SIGNAL ;
    PORT
      LAYER M4 ;
        RECT  0 11.484 0.192 11.508 ;
    END
  END g_t_6_u_stin__dr_i[7]
  PIN g_t_6_u_stin__dr_i[80]
    DIRECTION INPUT ;
    USE SIGNAL ;
    PORT
      LAYER M4 ;
        RECT  0 40.38 0.192 40.404 ;
    END
  END g_t_6_u_stin__dr_i[80]
  PIN g_t_6_u_stin__dr_i[81]
    DIRECTION INPUT ;
    USE SIGNAL ;
    PORT
      LAYER M4 ;
        RECT  0 40.812 0.192 40.836 ;
    END
  END g_t_6_u_stin__dr_i[81]
  PIN g_t_6_u_stin__dr_i[82]
    DIRECTION INPUT ;
    USE SIGNAL ;
    PORT
      LAYER M4 ;
        RECT  0 41.196 0.192 41.22 ;
    END
  END g_t_6_u_stin__dr_i[82]
  PIN g_t_6_u_stin__dr_i[83]
    DIRECTION INPUT ;
    USE SIGNAL ;
    PORT
      LAYER M4 ;
        RECT  0 41.58 0.192 41.604 ;
    END
  END g_t_6_u_stin__dr_i[83]
  PIN g_t_6_u_stin__dr_i[84]
    DIRECTION INPUT ;
    USE SIGNAL ;
    PORT
      LAYER M4 ;
        RECT  0 41.964 0.192 41.988 ;
    END
  END g_t_6_u_stin__dr_i[84]
  PIN g_t_6_u_stin__dr_i[85]
    DIRECTION INPUT ;
    USE SIGNAL ;
    PORT
      LAYER M4 ;
        RECT  0 42.396 0.192 42.42 ;
    END
  END g_t_6_u_stin__dr_i[85]
  PIN g_t_6_u_stin__dr_i[86]
    DIRECTION INPUT ;
    USE SIGNAL ;
    PORT
      LAYER M4 ;
        RECT  0 42.78 0.192 42.804 ;
    END
  END g_t_6_u_stin__dr_i[86]
  PIN g_t_6_u_stin__dr_i[87]
    DIRECTION INPUT ;
    USE SIGNAL ;
    PORT
      LAYER M4 ;
        RECT  0 43.164 0.192 43.188 ;
    END
  END g_t_6_u_stin__dr_i[87]
  PIN g_t_6_u_stin__dr_i[88]
    DIRECTION INPUT ;
    USE SIGNAL ;
    PORT
      LAYER M4 ;
        RECT  0 43.596 0.192 43.62 ;
    END
  END g_t_6_u_stin__dr_i[88]
  PIN g_t_6_u_stin__dr_i[89]
    DIRECTION INPUT ;
    USE SIGNAL ;
    PORT
      LAYER M4 ;
        RECT  0 43.98 0.192 44.004 ;
    END
  END g_t_6_u_stin__dr_i[89]
  PIN g_t_6_u_stin__dr_i[8]
    DIRECTION INPUT ;
    USE SIGNAL ;
    PORT
      LAYER M4 ;
        RECT  0 11.868 0.192 11.892 ;
    END
  END g_t_6_u_stin__dr_i[8]
  PIN g_t_6_u_stin__dr_i[90]
    DIRECTION INPUT ;
    USE SIGNAL ;
    PORT
      LAYER M4 ;
        RECT  0 44.364 0.192 44.388 ;
    END
  END g_t_6_u_stin__dr_i[90]
  PIN g_t_6_u_stin__dr_i[91]
    DIRECTION INPUT ;
    USE SIGNAL ;
    PORT
      LAYER M4 ;
        RECT  0 44.748 0.192 44.772 ;
    END
  END g_t_6_u_stin__dr_i[91]
  PIN g_t_6_u_stin__dr_i[92]
    DIRECTION INPUT ;
    USE SIGNAL ;
    PORT
      LAYER M4 ;
        RECT  0 45.18 0.192 45.204 ;
    END
  END g_t_6_u_stin__dr_i[92]
  PIN g_t_6_u_stin__dr_i[93]
    DIRECTION INPUT ;
    USE SIGNAL ;
    PORT
      LAYER M4 ;
        RECT  0 45.564 0.192 45.588 ;
    END
  END g_t_6_u_stin__dr_i[93]
  PIN g_t_6_u_stin__dr_i[94]
    DIRECTION INPUT ;
    USE SIGNAL ;
    PORT
      LAYER M4 ;
        RECT  0 45.948 0.192 45.972 ;
    END
  END g_t_6_u_stin__dr_i[94]
  PIN g_t_6_u_stin__dr_i[95]
    DIRECTION INPUT ;
    USE SIGNAL ;
    PORT
      LAYER M4 ;
        RECT  0 46.332 0.192 46.356 ;
    END
  END g_t_6_u_stin__dr_i[95]
  PIN g_t_6_u_stin__dr_i[96]
    DIRECTION INPUT ;
    USE SIGNAL ;
    PORT
      LAYER M4 ;
        RECT  0 46.764 0.192 46.788 ;
    END
  END g_t_6_u_stin__dr_i[96]
  PIN g_t_6_u_stin__dr_i[97]
    DIRECTION INPUT ;
    USE SIGNAL ;
    PORT
      LAYER M4 ;
        RECT  0 47.148 0.192 47.172 ;
    END
  END g_t_6_u_stin__dr_i[97]
  PIN g_t_6_u_stin__dr_i[98]
    DIRECTION INPUT ;
    USE SIGNAL ;
    PORT
      LAYER M4 ;
        RECT  0 47.532 0.192 47.556 ;
    END
  END g_t_6_u_stin__dr_i[98]
  PIN g_t_6_u_stin__dr_i[99]
    DIRECTION INPUT ;
    USE SIGNAL ;
    PORT
      LAYER M4 ;
        RECT  0 47.916 0.192 47.94 ;
    END
  END g_t_6_u_stin__dr_i[99]
  PIN g_t_6_u_stin__dr_i[9]
    DIRECTION INPUT ;
    USE SIGNAL ;
    PORT
      LAYER M4 ;
        RECT  0 12.252 0.192 12.276 ;
    END
  END g_t_6_u_stin__dr_i[9]
  PIN g_t_6_u_stin__rst_n[0]
    DIRECTION INPUT ;
    USE SIGNAL ;
    PORT
      LAYER M5 ;
        RECT  55.068 215.808 55.092 216 ;
    END
  END g_t_6_u_stin__rst_n[0]
  PIN g_t_6_u_stk__clk[0]
    DIRECTION INPUT ;
    USE SIGNAL ;
    PORT
      LAYER M5 ;
        RECT  76.236 215.808 76.26 216 ;
    END
  END g_t_6_u_stk__clk[0]
  PIN g_t_6_u_stk__gf_o[0]
    DIRECTION OUTPUT ;
    USE SIGNAL ;
    PORT
      LAYER M4 ;
        RECT  0 94.716 0.192 94.74 ;
    END
  END g_t_6_u_stk__gf_o[0]
  PIN g_t_6_u_stk__kp_o[0]
    DIRECTION OUTPUT ;
    USE SIGNAL ;
    PORT
      LAYER M4 ;
        RECT  0 95.1 0.192 95.124 ;
    END
  END g_t_6_u_stk__kp_o[0]
  PIN g_t_6_u_stk__kp_o[10]
    DIRECTION OUTPUT ;
    USE SIGNAL ;
    PORT
      LAYER M4 ;
        RECT  0 99.084 0.192 99.108 ;
    END
  END g_t_6_u_stk__kp_o[10]
  PIN g_t_6_u_stk__kp_o[11]
    DIRECTION OUTPUT ;
    USE SIGNAL ;
    PORT
      LAYER M4 ;
        RECT  0 99.468 0.192 99.492 ;
    END
  END g_t_6_u_stk__kp_o[11]
  PIN g_t_6_u_stk__kp_o[12]
    DIRECTION OUTPUT ;
    USE SIGNAL ;
    PORT
      LAYER M4 ;
        RECT  0 99.852 0.192 99.876 ;
    END
  END g_t_6_u_stk__kp_o[12]
  PIN g_t_6_u_stk__kp_o[13]
    DIRECTION OUTPUT ;
    USE SIGNAL ;
    PORT
      LAYER M4 ;
        RECT  0 100.236 0.192 100.26 ;
    END
  END g_t_6_u_stk__kp_o[13]
  PIN g_t_6_u_stk__kp_o[14]
    DIRECTION OUTPUT ;
    USE SIGNAL ;
    PORT
      LAYER M4 ;
        RECT  0 100.668 0.192 100.692 ;
    END
  END g_t_6_u_stk__kp_o[14]
  PIN g_t_6_u_stk__kp_o[15]
    DIRECTION OUTPUT ;
    USE SIGNAL ;
    PORT
      LAYER M4 ;
        RECT  0 101.052 0.192 101.076 ;
    END
  END g_t_6_u_stk__kp_o[15]
  PIN g_t_6_u_stk__kp_o[16]
    DIRECTION OUTPUT ;
    USE SIGNAL ;
    PORT
      LAYER M4 ;
        RECT  0 101.436 0.192 101.46 ;
    END
  END g_t_6_u_stk__kp_o[16]
  PIN g_t_6_u_stk__kp_o[17]
    DIRECTION OUTPUT ;
    USE SIGNAL ;
    PORT
      LAYER M4 ;
        RECT  0 101.82 0.192 101.844 ;
    END
  END g_t_6_u_stk__kp_o[17]
  PIN g_t_6_u_stk__kp_o[18]
    DIRECTION OUTPUT ;
    USE SIGNAL ;
    PORT
      LAYER M4 ;
        RECT  0 102.252 0.192 102.276 ;
    END
  END g_t_6_u_stk__kp_o[18]
  PIN g_t_6_u_stk__kp_o[19]
    DIRECTION OUTPUT ;
    USE SIGNAL ;
    PORT
      LAYER M4 ;
        RECT  0 102.636 0.192 102.66 ;
    END
  END g_t_6_u_stk__kp_o[19]
  PIN g_t_6_u_stk__kp_o[1]
    DIRECTION OUTPUT ;
    USE SIGNAL ;
    PORT
      LAYER M4 ;
        RECT  0 95.484 0.192 95.508 ;
    END
  END g_t_6_u_stk__kp_o[1]
  PIN g_t_6_u_stk__kp_o[20]
    DIRECTION OUTPUT ;
    USE SIGNAL ;
    PORT
      LAYER M4 ;
        RECT  0 103.02 0.192 103.044 ;
    END
  END g_t_6_u_stk__kp_o[20]
  PIN g_t_6_u_stk__kp_o[21]
    DIRECTION OUTPUT ;
    USE SIGNAL ;
    PORT
      LAYER M4 ;
        RECT  0 103.452 0.192 103.476 ;
    END
  END g_t_6_u_stk__kp_o[21]
  PIN g_t_6_u_stk__kp_o[22]
    DIRECTION OUTPUT ;
    USE SIGNAL ;
    PORT
      LAYER M4 ;
        RECT  0 103.836 0.192 103.86 ;
    END
  END g_t_6_u_stk__kp_o[22]
  PIN g_t_6_u_stk__kp_o[23]
    DIRECTION OUTPUT ;
    USE SIGNAL ;
    PORT
      LAYER M4 ;
        RECT  0 104.22 0.192 104.244 ;
    END
  END g_t_6_u_stk__kp_o[23]
  PIN g_t_6_u_stk__kp_o[24]
    DIRECTION OUTPUT ;
    USE SIGNAL ;
    PORT
      LAYER M4 ;
        RECT  0 104.604 0.192 104.628 ;
    END
  END g_t_6_u_stk__kp_o[24]
  PIN g_t_6_u_stk__kp_o[25]
    DIRECTION OUTPUT ;
    USE SIGNAL ;
    PORT
      LAYER M4 ;
        RECT  0 105.036 0.192 105.06 ;
    END
  END g_t_6_u_stk__kp_o[25]
  PIN g_t_6_u_stk__kp_o[26]
    DIRECTION OUTPUT ;
    USE SIGNAL ;
    PORT
      LAYER M4 ;
        RECT  0 105.42 0.192 105.444 ;
    END
  END g_t_6_u_stk__kp_o[26]
  PIN g_t_6_u_stk__kp_o[27]
    DIRECTION OUTPUT ;
    USE SIGNAL ;
    PORT
      LAYER M4 ;
        RECT  0 105.804 0.192 105.828 ;
    END
  END g_t_6_u_stk__kp_o[27]
  PIN g_t_6_u_stk__kp_o[28]
    DIRECTION OUTPUT ;
    USE SIGNAL ;
    PORT
      LAYER M4 ;
        RECT  0 106.188 0.192 106.212 ;
    END
  END g_t_6_u_stk__kp_o[28]
  PIN g_t_6_u_stk__kp_o[29]
    DIRECTION OUTPUT ;
    USE SIGNAL ;
    PORT
      LAYER M4 ;
        RECT  0 106.62 0.192 106.644 ;
    END
  END g_t_6_u_stk__kp_o[29]
  PIN g_t_6_u_stk__kp_o[2]
    DIRECTION OUTPUT ;
    USE SIGNAL ;
    PORT
      LAYER M4 ;
        RECT  0 95.916 0.192 95.94 ;
    END
  END g_t_6_u_stk__kp_o[2]
  PIN g_t_6_u_stk__kp_o[30]
    DIRECTION OUTPUT ;
    USE SIGNAL ;
    PORT
      LAYER M4 ;
        RECT  0 107.004 0.192 107.028 ;
    END
  END g_t_6_u_stk__kp_o[30]
  PIN g_t_6_u_stk__kp_o[31]
    DIRECTION OUTPUT ;
    USE SIGNAL ;
    PORT
      LAYER M4 ;
        RECT  0 107.388 0.192 107.412 ;
    END
  END g_t_6_u_stk__kp_o[31]
  PIN g_t_6_u_stk__kp_o[3]
    DIRECTION OUTPUT ;
    USE SIGNAL ;
    PORT
      LAYER M4 ;
        RECT  0 96.3 0.192 96.324 ;
    END
  END g_t_6_u_stk__kp_o[3]
  PIN g_t_6_u_stk__kp_o[4]
    DIRECTION OUTPUT ;
    USE SIGNAL ;
    PORT
      LAYER M4 ;
        RECT  0 96.684 0.192 96.708 ;
    END
  END g_t_6_u_stk__kp_o[4]
  PIN g_t_6_u_stk__kp_o[5]
    DIRECTION OUTPUT ;
    USE SIGNAL ;
    PORT
      LAYER M4 ;
        RECT  0 97.068 0.192 97.092 ;
    END
  END g_t_6_u_stk__kp_o[5]
  PIN g_t_6_u_stk__kp_o[6]
    DIRECTION OUTPUT ;
    USE SIGNAL ;
    PORT
      LAYER M4 ;
        RECT  0 97.5 0.192 97.524 ;
    END
  END g_t_6_u_stk__kp_o[6]
  PIN g_t_6_u_stk__kp_o[7]
    DIRECTION OUTPUT ;
    USE SIGNAL ;
    PORT
      LAYER M4 ;
        RECT  0 97.884 0.192 97.908 ;
    END
  END g_t_6_u_stk__kp_o[7]
  PIN g_t_6_u_stk__kp_o[8]
    DIRECTION OUTPUT ;
    USE SIGNAL ;
    PORT
      LAYER M4 ;
        RECT  0 98.268 0.192 98.292 ;
    END
  END g_t_6_u_stk__kp_o[8]
  PIN g_t_6_u_stk__kp_o[9]
    DIRECTION OUTPUT ;
    USE SIGNAL ;
    PORT
      LAYER M4 ;
        RECT  0 98.652 0.192 98.676 ;
    END
  END g_t_6_u_stk__kp_o[9]
  PIN g_t_6_u_stk__kpv_o[0]
    DIRECTION OUTPUT ;
    USE SIGNAL ;
    PORT
      LAYER M4 ;
        RECT  0 107.772 0.192 107.796 ;
    END
  END g_t_6_u_stk__kpv_o[0]
  PIN g_t_6_u_stk__rst_n[0]
    DIRECTION INPUT ;
    USE SIGNAL ;
    PORT
      LAYER M5 ;
        RECT  97.404 215.808 97.428 216 ;
    END
  END g_t_6_u_stk__rst_n[0]
  PIN g_t_7_u_l8__clk[0]
    DIRECTION INPUT ;
    USE SIGNAL ;
    PORT
      LAYER M5 ;
        RECT  118.572 215.808 118.596 216 ;
    END
  END g_t_7_u_l8__clk[0]
  PIN g_t_7_u_stin__clk[0]
    DIRECTION INPUT ;
    USE SIGNAL ;
    PORT
      LAYER M5 ;
        RECT  139.74 215.808 139.764 216 ;
    END
  END g_t_7_u_stin__clk[0]
  PIN g_t_7_u_stin__cr_i[0]
    DIRECTION INPUT ;
    USE SIGNAL ;
    PORT
      LAYER M4 ;
        RECT  0 108.204 0.192 108.228 ;
    END
  END g_t_7_u_stin__cr_i[0]
  PIN g_t_7_u_stin__cr_i[10]
    DIRECTION INPUT ;
    USE SIGNAL ;
    PORT
      LAYER M4 ;
        RECT  0 112.14 0.192 112.164 ;
    END
  END g_t_7_u_stin__cr_i[10]
  PIN g_t_7_u_stin__cr_i[11]
    DIRECTION INPUT ;
    USE SIGNAL ;
    PORT
      LAYER M4 ;
        RECT  0 112.524 0.192 112.548 ;
    END
  END g_t_7_u_stin__cr_i[11]
  PIN g_t_7_u_stin__cr_i[12]
    DIRECTION INPUT ;
    USE SIGNAL ;
    PORT
      LAYER M4 ;
        RECT  0 112.956 0.192 112.98 ;
    END
  END g_t_7_u_stin__cr_i[12]
  PIN g_t_7_u_stin__cr_i[13]
    DIRECTION INPUT ;
    USE SIGNAL ;
    PORT
      LAYER M4 ;
        RECT  0 113.34 0.192 113.364 ;
    END
  END g_t_7_u_stin__cr_i[13]
  PIN g_t_7_u_stin__cr_i[14]
    DIRECTION INPUT ;
    USE SIGNAL ;
    PORT
      LAYER M4 ;
        RECT  0 113.724 0.192 113.748 ;
    END
  END g_t_7_u_stin__cr_i[14]
  PIN g_t_7_u_stin__cr_i[15]
    DIRECTION INPUT ;
    USE SIGNAL ;
    PORT
      LAYER M4 ;
        RECT  0 114.156 0.192 114.18 ;
    END
  END g_t_7_u_stin__cr_i[15]
  PIN g_t_7_u_stin__cr_i[1]
    DIRECTION INPUT ;
    USE SIGNAL ;
    PORT
      LAYER M4 ;
        RECT  0 108.588 0.192 108.612 ;
    END
  END g_t_7_u_stin__cr_i[1]
  PIN g_t_7_u_stin__cr_i[2]
    DIRECTION INPUT ;
    USE SIGNAL ;
    PORT
      LAYER M4 ;
        RECT  0 108.972 0.192 108.996 ;
    END
  END g_t_7_u_stin__cr_i[2]
  PIN g_t_7_u_stin__cr_i[3]
    DIRECTION INPUT ;
    USE SIGNAL ;
    PORT
      LAYER M4 ;
        RECT  0 109.356 0.192 109.38 ;
    END
  END g_t_7_u_stin__cr_i[3]
  PIN g_t_7_u_stin__cr_i[4]
    DIRECTION INPUT ;
    USE SIGNAL ;
    PORT
      LAYER M4 ;
        RECT  0 109.788 0.192 109.812 ;
    END
  END g_t_7_u_stin__cr_i[4]
  PIN g_t_7_u_stin__cr_i[5]
    DIRECTION INPUT ;
    USE SIGNAL ;
    PORT
      LAYER M4 ;
        RECT  0 110.172 0.192 110.196 ;
    END
  END g_t_7_u_stin__cr_i[5]
  PIN g_t_7_u_stin__cr_i[6]
    DIRECTION INPUT ;
    USE SIGNAL ;
    PORT
      LAYER M4 ;
        RECT  0 110.556 0.192 110.58 ;
    END
  END g_t_7_u_stin__cr_i[6]
  PIN g_t_7_u_stin__cr_i[7]
    DIRECTION INPUT ;
    USE SIGNAL ;
    PORT
      LAYER M4 ;
        RECT  0 110.94 0.192 110.964 ;
    END
  END g_t_7_u_stin__cr_i[7]
  PIN g_t_7_u_stin__cr_i[8]
    DIRECTION INPUT ;
    USE SIGNAL ;
    PORT
      LAYER M4 ;
        RECT  0 111.372 0.192 111.396 ;
    END
  END g_t_7_u_stin__cr_i[8]
  PIN g_t_7_u_stin__cr_i[9]
    DIRECTION INPUT ;
    USE SIGNAL ;
    PORT
      LAYER M4 ;
        RECT  0 111.756 0.192 111.78 ;
    END
  END g_t_7_u_stin__cr_i[9]
  PIN g_t_7_u_stin__dr_i[0]
    DIRECTION INPUT ;
    USE SIGNAL ;
    PORT
      LAYER M4 ;
        RECT  0 114.54 0.192 114.564 ;
    END
  END g_t_7_u_stin__dr_i[0]
  PIN g_t_7_u_stin__dr_i[100]
    DIRECTION INPUT ;
    USE SIGNAL ;
    PORT
      LAYER M4 ;
        RECT  0 154.188 0.192 154.212 ;
    END
  END g_t_7_u_stin__dr_i[100]
  PIN g_t_7_u_stin__dr_i[101]
    DIRECTION INPUT ;
    USE SIGNAL ;
    PORT
      LAYER M4 ;
        RECT  0 154.572 0.192 154.596 ;
    END
  END g_t_7_u_stin__dr_i[101]
  PIN g_t_7_u_stin__dr_i[102]
    DIRECTION INPUT ;
    USE SIGNAL ;
    PORT
      LAYER M4 ;
        RECT  0 154.956 0.192 154.98 ;
    END
  END g_t_7_u_stin__dr_i[102]
  PIN g_t_7_u_stin__dr_i[103]
    DIRECTION INPUT ;
    USE SIGNAL ;
    PORT
      LAYER M4 ;
        RECT  0 155.34 0.192 155.364 ;
    END
  END g_t_7_u_stin__dr_i[103]
  PIN g_t_7_u_stin__dr_i[104]
    DIRECTION INPUT ;
    USE SIGNAL ;
    PORT
      LAYER M4 ;
        RECT  0 155.772 0.192 155.796 ;
    END
  END g_t_7_u_stin__dr_i[104]
  PIN g_t_7_u_stin__dr_i[105]
    DIRECTION INPUT ;
    USE SIGNAL ;
    PORT
      LAYER M4 ;
        RECT  0 156.156 0.192 156.18 ;
    END
  END g_t_7_u_stin__dr_i[105]
  PIN g_t_7_u_stin__dr_i[106]
    DIRECTION INPUT ;
    USE SIGNAL ;
    PORT
      LAYER M4 ;
        RECT  0 156.54 0.192 156.564 ;
    END
  END g_t_7_u_stin__dr_i[106]
  PIN g_t_7_u_stin__dr_i[107]
    DIRECTION INPUT ;
    USE SIGNAL ;
    PORT
      LAYER M4 ;
        RECT  0 156.924 0.192 156.948 ;
    END
  END g_t_7_u_stin__dr_i[107]
  PIN g_t_7_u_stin__dr_i[108]
    DIRECTION INPUT ;
    USE SIGNAL ;
    PORT
      LAYER M4 ;
        RECT  0 157.356 0.192 157.38 ;
    END
  END g_t_7_u_stin__dr_i[108]
  PIN g_t_7_u_stin__dr_i[109]
    DIRECTION INPUT ;
    USE SIGNAL ;
    PORT
      LAYER M4 ;
        RECT  0 157.74 0.192 157.764 ;
    END
  END g_t_7_u_stin__dr_i[109]
  PIN g_t_7_u_stin__dr_i[10]
    DIRECTION INPUT ;
    USE SIGNAL ;
    PORT
      LAYER M4 ;
        RECT  0 118.476 0.192 118.5 ;
    END
  END g_t_7_u_stin__dr_i[10]
  PIN g_t_7_u_stin__dr_i[110]
    DIRECTION INPUT ;
    USE SIGNAL ;
    PORT
      LAYER M4 ;
        RECT  0 158.124 0.192 158.148 ;
    END
  END g_t_7_u_stin__dr_i[110]
  PIN g_t_7_u_stin__dr_i[111]
    DIRECTION INPUT ;
    USE SIGNAL ;
    PORT
      LAYER M4 ;
        RECT  0 158.508 0.192 158.532 ;
    END
  END g_t_7_u_stin__dr_i[111]
  PIN g_t_7_u_stin__dr_i[112]
    DIRECTION INPUT ;
    USE SIGNAL ;
    PORT
      LAYER M4 ;
        RECT  0 158.94 0.192 158.964 ;
    END
  END g_t_7_u_stin__dr_i[112]
  PIN g_t_7_u_stin__dr_i[113]
    DIRECTION INPUT ;
    USE SIGNAL ;
    PORT
      LAYER M4 ;
        RECT  0 159.324 0.192 159.348 ;
    END
  END g_t_7_u_stin__dr_i[113]
  PIN g_t_7_u_stin__dr_i[114]
    DIRECTION INPUT ;
    USE SIGNAL ;
    PORT
      LAYER M4 ;
        RECT  0 159.708 0.192 159.732 ;
    END
  END g_t_7_u_stin__dr_i[114]
  PIN g_t_7_u_stin__dr_i[115]
    DIRECTION INPUT ;
    USE SIGNAL ;
    PORT
      LAYER M4 ;
        RECT  0 160.092 0.192 160.116 ;
    END
  END g_t_7_u_stin__dr_i[115]
  PIN g_t_7_u_stin__dr_i[116]
    DIRECTION INPUT ;
    USE SIGNAL ;
    PORT
      LAYER M4 ;
        RECT  0 160.524 0.192 160.548 ;
    END
  END g_t_7_u_stin__dr_i[116]
  PIN g_t_7_u_stin__dr_i[117]
    DIRECTION INPUT ;
    USE SIGNAL ;
    PORT
      LAYER M4 ;
        RECT  0 160.908 0.192 160.932 ;
    END
  END g_t_7_u_stin__dr_i[117]
  PIN g_t_7_u_stin__dr_i[118]
    DIRECTION INPUT ;
    USE SIGNAL ;
    PORT
      LAYER M4 ;
        RECT  0 161.292 0.192 161.316 ;
    END
  END g_t_7_u_stin__dr_i[118]
  PIN g_t_7_u_stin__dr_i[119]
    DIRECTION INPUT ;
    USE SIGNAL ;
    PORT
      LAYER M4 ;
        RECT  0 161.724 0.192 161.748 ;
    END
  END g_t_7_u_stin__dr_i[119]
  PIN g_t_7_u_stin__dr_i[11]
    DIRECTION INPUT ;
    USE SIGNAL ;
    PORT
      LAYER M4 ;
        RECT  0 118.908 0.192 118.932 ;
    END
  END g_t_7_u_stin__dr_i[11]
  PIN g_t_7_u_stin__dr_i[120]
    DIRECTION INPUT ;
    USE SIGNAL ;
    PORT
      LAYER M4 ;
        RECT  0 162.108 0.192 162.132 ;
    END
  END g_t_7_u_stin__dr_i[120]
  PIN g_t_7_u_stin__dr_i[121]
    DIRECTION INPUT ;
    USE SIGNAL ;
    PORT
      LAYER M4 ;
        RECT  0 162.492 0.192 162.516 ;
    END
  END g_t_7_u_stin__dr_i[121]
  PIN g_t_7_u_stin__dr_i[122]
    DIRECTION INPUT ;
    USE SIGNAL ;
    PORT
      LAYER M4 ;
        RECT  0 162.876 0.192 162.9 ;
    END
  END g_t_7_u_stin__dr_i[122]
  PIN g_t_7_u_stin__dr_i[123]
    DIRECTION INPUT ;
    USE SIGNAL ;
    PORT
      LAYER M4 ;
        RECT  0 163.308 0.192 163.332 ;
    END
  END g_t_7_u_stin__dr_i[123]
  PIN g_t_7_u_stin__dr_i[124]
    DIRECTION INPUT ;
    USE SIGNAL ;
    PORT
      LAYER M4 ;
        RECT  0 163.692 0.192 163.716 ;
    END
  END g_t_7_u_stin__dr_i[124]
  PIN g_t_7_u_stin__dr_i[125]
    DIRECTION INPUT ;
    USE SIGNAL ;
    PORT
      LAYER M4 ;
        RECT  0 164.076 0.192 164.1 ;
    END
  END g_t_7_u_stin__dr_i[125]
  PIN g_t_7_u_stin__dr_i[126]
    DIRECTION INPUT ;
    USE SIGNAL ;
    PORT
      LAYER M4 ;
        RECT  0 164.46 0.192 164.484 ;
    END
  END g_t_7_u_stin__dr_i[126]
  PIN g_t_7_u_stin__dr_i[127]
    DIRECTION INPUT ;
    USE SIGNAL ;
    PORT
      LAYER M4 ;
        RECT  0 164.892 0.192 164.916 ;
    END
  END g_t_7_u_stin__dr_i[127]
  PIN g_t_7_u_stin__dr_i[128]
    DIRECTION INPUT ;
    USE SIGNAL ;
    PORT
      LAYER M4 ;
        RECT  0 165.276 0.192 165.3 ;
    END
  END g_t_7_u_stin__dr_i[128]
  PIN g_t_7_u_stin__dr_i[129]
    DIRECTION INPUT ;
    USE SIGNAL ;
    PORT
      LAYER M4 ;
        RECT  0 165.66 0.192 165.684 ;
    END
  END g_t_7_u_stin__dr_i[129]
  PIN g_t_7_u_stin__dr_i[12]
    DIRECTION INPUT ;
    USE SIGNAL ;
    PORT
      LAYER M4 ;
        RECT  0 119.292 0.192 119.316 ;
    END
  END g_t_7_u_stin__dr_i[12]
  PIN g_t_7_u_stin__dr_i[130]
    DIRECTION INPUT ;
    USE SIGNAL ;
    PORT
      LAYER M4 ;
        RECT  0 166.044 0.192 166.068 ;
    END
  END g_t_7_u_stin__dr_i[130]
  PIN g_t_7_u_stin__dr_i[131]
    DIRECTION INPUT ;
    USE SIGNAL ;
    PORT
      LAYER M4 ;
        RECT  0 166.476 0.192 166.5 ;
    END
  END g_t_7_u_stin__dr_i[131]
  PIN g_t_7_u_stin__dr_i[132]
    DIRECTION INPUT ;
    USE SIGNAL ;
    PORT
      LAYER M4 ;
        RECT  0 166.86 0.192 166.884 ;
    END
  END g_t_7_u_stin__dr_i[132]
  PIN g_t_7_u_stin__dr_i[133]
    DIRECTION INPUT ;
    USE SIGNAL ;
    PORT
      LAYER M4 ;
        RECT  0 167.244 0.192 167.268 ;
    END
  END g_t_7_u_stin__dr_i[133]
  PIN g_t_7_u_stin__dr_i[134]
    DIRECTION INPUT ;
    USE SIGNAL ;
    PORT
      LAYER M4 ;
        RECT  0 167.628 0.192 167.652 ;
    END
  END g_t_7_u_stin__dr_i[134]
  PIN g_t_7_u_stin__dr_i[135]
    DIRECTION INPUT ;
    USE SIGNAL ;
    PORT
      LAYER M4 ;
        RECT  0 168.06 0.192 168.084 ;
    END
  END g_t_7_u_stin__dr_i[135]
  PIN g_t_7_u_stin__dr_i[136]
    DIRECTION INPUT ;
    USE SIGNAL ;
    PORT
      LAYER M4 ;
        RECT  0 168.444 0.192 168.468 ;
    END
  END g_t_7_u_stin__dr_i[136]
  PIN g_t_7_u_stin__dr_i[137]
    DIRECTION INPUT ;
    USE SIGNAL ;
    PORT
      LAYER M4 ;
        RECT  0 168.828 0.192 168.852 ;
    END
  END g_t_7_u_stin__dr_i[137]
  PIN g_t_7_u_stin__dr_i[138]
    DIRECTION INPUT ;
    USE SIGNAL ;
    PORT
      LAYER M4 ;
        RECT  0 169.212 0.192 169.236 ;
    END
  END g_t_7_u_stin__dr_i[138]
  PIN g_t_7_u_stin__dr_i[139]
    DIRECTION INPUT ;
    USE SIGNAL ;
    PORT
      LAYER M4 ;
        RECT  0 169.644 0.192 169.668 ;
    END
  END g_t_7_u_stin__dr_i[139]
  PIN g_t_7_u_stin__dr_i[13]
    DIRECTION INPUT ;
    USE SIGNAL ;
    PORT
      LAYER M4 ;
        RECT  0 119.676 0.192 119.7 ;
    END
  END g_t_7_u_stin__dr_i[13]
  PIN g_t_7_u_stin__dr_i[140]
    DIRECTION INPUT ;
    USE SIGNAL ;
    PORT
      LAYER M4 ;
        RECT  0 170.028 0.192 170.052 ;
    END
  END g_t_7_u_stin__dr_i[140]
  PIN g_t_7_u_stin__dr_i[141]
    DIRECTION INPUT ;
    USE SIGNAL ;
    PORT
      LAYER M4 ;
        RECT  0 170.412 0.192 170.436 ;
    END
  END g_t_7_u_stin__dr_i[141]
  PIN g_t_7_u_stin__dr_i[142]
    DIRECTION INPUT ;
    USE SIGNAL ;
    PORT
      LAYER M4 ;
        RECT  0 170.796 0.192 170.82 ;
    END
  END g_t_7_u_stin__dr_i[142]
  PIN g_t_7_u_stin__dr_i[143]
    DIRECTION INPUT ;
    USE SIGNAL ;
    PORT
      LAYER M4 ;
        RECT  0 171.228 0.192 171.252 ;
    END
  END g_t_7_u_stin__dr_i[143]
  PIN g_t_7_u_stin__dr_i[144]
    DIRECTION INPUT ;
    USE SIGNAL ;
    PORT
      LAYER M4 ;
        RECT  0 171.612 0.192 171.636 ;
    END
  END g_t_7_u_stin__dr_i[144]
  PIN g_t_7_u_stin__dr_i[145]
    DIRECTION INPUT ;
    USE SIGNAL ;
    PORT
      LAYER M4 ;
        RECT  0 171.996 0.192 172.02 ;
    END
  END g_t_7_u_stin__dr_i[145]
  PIN g_t_7_u_stin__dr_i[146]
    DIRECTION INPUT ;
    USE SIGNAL ;
    PORT
      LAYER M4 ;
        RECT  0 172.38 0.192 172.404 ;
    END
  END g_t_7_u_stin__dr_i[146]
  PIN g_t_7_u_stin__dr_i[147]
    DIRECTION INPUT ;
    USE SIGNAL ;
    PORT
      LAYER M4 ;
        RECT  0 172.812 0.192 172.836 ;
    END
  END g_t_7_u_stin__dr_i[147]
  PIN g_t_7_u_stin__dr_i[148]
    DIRECTION INPUT ;
    USE SIGNAL ;
    PORT
      LAYER M4 ;
        RECT  0 173.196 0.192 173.22 ;
    END
  END g_t_7_u_stin__dr_i[148]
  PIN g_t_7_u_stin__dr_i[149]
    DIRECTION INPUT ;
    USE SIGNAL ;
    PORT
      LAYER M4 ;
        RECT  0 173.58 0.192 173.604 ;
    END
  END g_t_7_u_stin__dr_i[149]
  PIN g_t_7_u_stin__dr_i[14]
    DIRECTION INPUT ;
    USE SIGNAL ;
    PORT
      LAYER M4 ;
        RECT  0 120.06 0.192 120.084 ;
    END
  END g_t_7_u_stin__dr_i[14]
  PIN g_t_7_u_stin__dr_i[150]
    DIRECTION INPUT ;
    USE SIGNAL ;
    PORT
      LAYER M4 ;
        RECT  0 174.012 0.192 174.036 ;
    END
  END g_t_7_u_stin__dr_i[150]
  PIN g_t_7_u_stin__dr_i[151]
    DIRECTION INPUT ;
    USE SIGNAL ;
    PORT
      LAYER M4 ;
        RECT  0 174.396 0.192 174.42 ;
    END
  END g_t_7_u_stin__dr_i[151]
  PIN g_t_7_u_stin__dr_i[152]
    DIRECTION INPUT ;
    USE SIGNAL ;
    PORT
      LAYER M4 ;
        RECT  0 174.78 0.192 174.804 ;
    END
  END g_t_7_u_stin__dr_i[152]
  PIN g_t_7_u_stin__dr_i[153]
    DIRECTION INPUT ;
    USE SIGNAL ;
    PORT
      LAYER M4 ;
        RECT  0 175.164 0.192 175.188 ;
    END
  END g_t_7_u_stin__dr_i[153]
  PIN g_t_7_u_stin__dr_i[154]
    DIRECTION INPUT ;
    USE SIGNAL ;
    PORT
      LAYER M4 ;
        RECT  0 175.596 0.192 175.62 ;
    END
  END g_t_7_u_stin__dr_i[154]
  PIN g_t_7_u_stin__dr_i[155]
    DIRECTION INPUT ;
    USE SIGNAL ;
    PORT
      LAYER M4 ;
        RECT  0 175.98 0.192 176.004 ;
    END
  END g_t_7_u_stin__dr_i[155]
  PIN g_t_7_u_stin__dr_i[156]
    DIRECTION INPUT ;
    USE SIGNAL ;
    PORT
      LAYER M4 ;
        RECT  0 176.364 0.192 176.388 ;
    END
  END g_t_7_u_stin__dr_i[156]
  PIN g_t_7_u_stin__dr_i[157]
    DIRECTION INPUT ;
    USE SIGNAL ;
    PORT
      LAYER M4 ;
        RECT  0 176.748 0.192 176.772 ;
    END
  END g_t_7_u_stin__dr_i[157]
  PIN g_t_7_u_stin__dr_i[158]
    DIRECTION INPUT ;
    USE SIGNAL ;
    PORT
      LAYER M4 ;
        RECT  0 177.18 0.192 177.204 ;
    END
  END g_t_7_u_stin__dr_i[158]
  PIN g_t_7_u_stin__dr_i[159]
    DIRECTION INPUT ;
    USE SIGNAL ;
    PORT
      LAYER M4 ;
        RECT  0 177.564 0.192 177.588 ;
    END
  END g_t_7_u_stin__dr_i[159]
  PIN g_t_7_u_stin__dr_i[15]
    DIRECTION INPUT ;
    USE SIGNAL ;
    PORT
      LAYER M4 ;
        RECT  0 120.492 0.192 120.516 ;
    END
  END g_t_7_u_stin__dr_i[15]
  PIN g_t_7_u_stin__dr_i[160]
    DIRECTION INPUT ;
    USE SIGNAL ;
    PORT
      LAYER M4 ;
        RECT  0 177.948 0.192 177.972 ;
    END
  END g_t_7_u_stin__dr_i[160]
  PIN g_t_7_u_stin__dr_i[161]
    DIRECTION INPUT ;
    USE SIGNAL ;
    PORT
      LAYER M4 ;
        RECT  0 178.332 0.192 178.356 ;
    END
  END g_t_7_u_stin__dr_i[161]
  PIN g_t_7_u_stin__dr_i[162]
    DIRECTION INPUT ;
    USE SIGNAL ;
    PORT
      LAYER M4 ;
        RECT  0 178.764 0.192 178.788 ;
    END
  END g_t_7_u_stin__dr_i[162]
  PIN g_t_7_u_stin__dr_i[163]
    DIRECTION INPUT ;
    USE SIGNAL ;
    PORT
      LAYER M4 ;
        RECT  0 179.148 0.192 179.172 ;
    END
  END g_t_7_u_stin__dr_i[163]
  PIN g_t_7_u_stin__dr_i[164]
    DIRECTION INPUT ;
    USE SIGNAL ;
    PORT
      LAYER M4 ;
        RECT  0 179.532 0.192 179.556 ;
    END
  END g_t_7_u_stin__dr_i[164]
  PIN g_t_7_u_stin__dr_i[165]
    DIRECTION INPUT ;
    USE SIGNAL ;
    PORT
      LAYER M4 ;
        RECT  0 179.916 0.192 179.94 ;
    END
  END g_t_7_u_stin__dr_i[165]
  PIN g_t_7_u_stin__dr_i[166]
    DIRECTION INPUT ;
    USE SIGNAL ;
    PORT
      LAYER M4 ;
        RECT  0 180.348 0.192 180.372 ;
    END
  END g_t_7_u_stin__dr_i[166]
  PIN g_t_7_u_stin__dr_i[167]
    DIRECTION INPUT ;
    USE SIGNAL ;
    PORT
      LAYER M4 ;
        RECT  0 180.732 0.192 180.756 ;
    END
  END g_t_7_u_stin__dr_i[167]
  PIN g_t_7_u_stin__dr_i[168]
    DIRECTION INPUT ;
    USE SIGNAL ;
    PORT
      LAYER M4 ;
        RECT  0 181.116 0.192 181.14 ;
    END
  END g_t_7_u_stin__dr_i[168]
  PIN g_t_7_u_stin__dr_i[169]
    DIRECTION INPUT ;
    USE SIGNAL ;
    PORT
      LAYER M4 ;
        RECT  0 181.5 0.192 181.524 ;
    END
  END g_t_7_u_stin__dr_i[169]
  PIN g_t_7_u_stin__dr_i[16]
    DIRECTION INPUT ;
    USE SIGNAL ;
    PORT
      LAYER M4 ;
        RECT  0 120.876 0.192 120.9 ;
    END
  END g_t_7_u_stin__dr_i[16]
  PIN g_t_7_u_stin__dr_i[170]
    DIRECTION INPUT ;
    USE SIGNAL ;
    PORT
      LAYER M4 ;
        RECT  0 181.932 0.192 181.956 ;
    END
  END g_t_7_u_stin__dr_i[170]
  PIN g_t_7_u_stin__dr_i[171]
    DIRECTION INPUT ;
    USE SIGNAL ;
    PORT
      LAYER M4 ;
        RECT  0 182.316 0.192 182.34 ;
    END
  END g_t_7_u_stin__dr_i[171]
  PIN g_t_7_u_stin__dr_i[172]
    DIRECTION INPUT ;
    USE SIGNAL ;
    PORT
      LAYER M4 ;
        RECT  0 182.7 0.192 182.724 ;
    END
  END g_t_7_u_stin__dr_i[172]
  PIN g_t_7_u_stin__dr_i[173]
    DIRECTION INPUT ;
    USE SIGNAL ;
    PORT
      LAYER M4 ;
        RECT  0 183.084 0.192 183.108 ;
    END
  END g_t_7_u_stin__dr_i[173]
  PIN g_t_7_u_stin__dr_i[174]
    DIRECTION INPUT ;
    USE SIGNAL ;
    PORT
      LAYER M4 ;
        RECT  0 183.516 0.192 183.54 ;
    END
  END g_t_7_u_stin__dr_i[174]
  PIN g_t_7_u_stin__dr_i[175]
    DIRECTION INPUT ;
    USE SIGNAL ;
    PORT
      LAYER M4 ;
        RECT  0 183.9 0.192 183.924 ;
    END
  END g_t_7_u_stin__dr_i[175]
  PIN g_t_7_u_stin__dr_i[176]
    DIRECTION INPUT ;
    USE SIGNAL ;
    PORT
      LAYER M4 ;
        RECT  0 184.284 0.192 184.308 ;
    END
  END g_t_7_u_stin__dr_i[176]
  PIN g_t_7_u_stin__dr_i[177]
    DIRECTION INPUT ;
    USE SIGNAL ;
    PORT
      LAYER M4 ;
        RECT  0 184.716 0.192 184.74 ;
    END
  END g_t_7_u_stin__dr_i[177]
  PIN g_t_7_u_stin__dr_i[178]
    DIRECTION INPUT ;
    USE SIGNAL ;
    PORT
      LAYER M4 ;
        RECT  0 185.1 0.192 185.124 ;
    END
  END g_t_7_u_stin__dr_i[178]
  PIN g_t_7_u_stin__dr_i[179]
    DIRECTION INPUT ;
    USE SIGNAL ;
    PORT
      LAYER M4 ;
        RECT  0 185.484 0.192 185.508 ;
    END
  END g_t_7_u_stin__dr_i[179]
  PIN g_t_7_u_stin__dr_i[17]
    DIRECTION INPUT ;
    USE SIGNAL ;
    PORT
      LAYER M4 ;
        RECT  0 121.26 0.192 121.284 ;
    END
  END g_t_7_u_stin__dr_i[17]
  PIN g_t_7_u_stin__dr_i[180]
    DIRECTION INPUT ;
    USE SIGNAL ;
    PORT
      LAYER M4 ;
        RECT  0 185.868 0.192 185.892 ;
    END
  END g_t_7_u_stin__dr_i[180]
  PIN g_t_7_u_stin__dr_i[181]
    DIRECTION INPUT ;
    USE SIGNAL ;
    PORT
      LAYER M4 ;
        RECT  0 186.3 0.192 186.324 ;
    END
  END g_t_7_u_stin__dr_i[181]
  PIN g_t_7_u_stin__dr_i[182]
    DIRECTION INPUT ;
    USE SIGNAL ;
    PORT
      LAYER M4 ;
        RECT  0 186.684 0.192 186.708 ;
    END
  END g_t_7_u_stin__dr_i[182]
  PIN g_t_7_u_stin__dr_i[183]
    DIRECTION INPUT ;
    USE SIGNAL ;
    PORT
      LAYER M4 ;
        RECT  0 187.068 0.192 187.092 ;
    END
  END g_t_7_u_stin__dr_i[183]
  PIN g_t_7_u_stin__dr_i[184]
    DIRECTION INPUT ;
    USE SIGNAL ;
    PORT
      LAYER M4 ;
        RECT  0 187.452 0.192 187.476 ;
    END
  END g_t_7_u_stin__dr_i[184]
  PIN g_t_7_u_stin__dr_i[185]
    DIRECTION INPUT ;
    USE SIGNAL ;
    PORT
      LAYER M4 ;
        RECT  0 187.884 0.192 187.908 ;
    END
  END g_t_7_u_stin__dr_i[185]
  PIN g_t_7_u_stin__dr_i[186]
    DIRECTION INPUT ;
    USE SIGNAL ;
    PORT
      LAYER M4 ;
        RECT  0 188.268 0.192 188.292 ;
    END
  END g_t_7_u_stin__dr_i[186]
  PIN g_t_7_u_stin__dr_i[187]
    DIRECTION INPUT ;
    USE SIGNAL ;
    PORT
      LAYER M4 ;
        RECT  0 188.652 0.192 188.676 ;
    END
  END g_t_7_u_stin__dr_i[187]
  PIN g_t_7_u_stin__dr_i[188]
    DIRECTION INPUT ;
    USE SIGNAL ;
    PORT
      LAYER M4 ;
        RECT  0 189.036 0.192 189.06 ;
    END
  END g_t_7_u_stin__dr_i[188]
  PIN g_t_7_u_stin__dr_i[189]
    DIRECTION INPUT ;
    USE SIGNAL ;
    PORT
      LAYER M4 ;
        RECT  0 189.468 0.192 189.492 ;
    END
  END g_t_7_u_stin__dr_i[189]
  PIN g_t_7_u_stin__dr_i[18]
    DIRECTION INPUT ;
    USE SIGNAL ;
    PORT
      LAYER M4 ;
        RECT  0 121.644 0.192 121.668 ;
    END
  END g_t_7_u_stin__dr_i[18]
  PIN g_t_7_u_stin__dr_i[190]
    DIRECTION INPUT ;
    USE SIGNAL ;
    PORT
      LAYER M4 ;
        RECT  0 189.852 0.192 189.876 ;
    END
  END g_t_7_u_stin__dr_i[190]
  PIN g_t_7_u_stin__dr_i[191]
    DIRECTION INPUT ;
    USE SIGNAL ;
    PORT
      LAYER M4 ;
        RECT  0 190.236 0.192 190.26 ;
    END
  END g_t_7_u_stin__dr_i[191]
  PIN g_t_7_u_stin__dr_i[192]
    DIRECTION INPUT ;
    USE SIGNAL ;
    PORT
      LAYER M4 ;
        RECT  0 190.62 0.192 190.644 ;
    END
  END g_t_7_u_stin__dr_i[192]
  PIN g_t_7_u_stin__dr_i[193]
    DIRECTION INPUT ;
    USE SIGNAL ;
    PORT
      LAYER M4 ;
        RECT  0 191.052 0.192 191.076 ;
    END
  END g_t_7_u_stin__dr_i[193]
  PIN g_t_7_u_stin__dr_i[194]
    DIRECTION INPUT ;
    USE SIGNAL ;
    PORT
      LAYER M4 ;
        RECT  0 191.436 0.192 191.46 ;
    END
  END g_t_7_u_stin__dr_i[194]
  PIN g_t_7_u_stin__dr_i[195]
    DIRECTION INPUT ;
    USE SIGNAL ;
    PORT
      LAYER M4 ;
        RECT  0 191.82 0.192 191.844 ;
    END
  END g_t_7_u_stin__dr_i[195]
  PIN g_t_7_u_stin__dr_i[196]
    DIRECTION INPUT ;
    USE SIGNAL ;
    PORT
      LAYER M4 ;
        RECT  0 192.204 0.192 192.228 ;
    END
  END g_t_7_u_stin__dr_i[196]
  PIN g_t_7_u_stin__dr_i[197]
    DIRECTION INPUT ;
    USE SIGNAL ;
    PORT
      LAYER M4 ;
        RECT  0 192.636 0.192 192.66 ;
    END
  END g_t_7_u_stin__dr_i[197]
  PIN g_t_7_u_stin__dr_i[198]
    DIRECTION INPUT ;
    USE SIGNAL ;
    PORT
      LAYER M4 ;
        RECT  0 193.02 0.192 193.044 ;
    END
  END g_t_7_u_stin__dr_i[198]
  PIN g_t_7_u_stin__dr_i[199]
    DIRECTION INPUT ;
    USE SIGNAL ;
    PORT
      LAYER M4 ;
        RECT  0 193.404 0.192 193.428 ;
    END
  END g_t_7_u_stin__dr_i[199]
  PIN g_t_7_u_stin__dr_i[19]
    DIRECTION INPUT ;
    USE SIGNAL ;
    PORT
      LAYER M4 ;
        RECT  0 122.076 0.192 122.1 ;
    END
  END g_t_7_u_stin__dr_i[19]
  PIN g_t_7_u_stin__dr_i[1]
    DIRECTION INPUT ;
    USE SIGNAL ;
    PORT
      LAYER M4 ;
        RECT  0 114.924 0.192 114.948 ;
    END
  END g_t_7_u_stin__dr_i[1]
  PIN g_t_7_u_stin__dr_i[200]
    DIRECTION INPUT ;
    USE SIGNAL ;
    PORT
      LAYER M4 ;
        RECT  0 193.788 0.192 193.812 ;
    END
  END g_t_7_u_stin__dr_i[200]
  PIN g_t_7_u_stin__dr_i[201]
    DIRECTION INPUT ;
    USE SIGNAL ;
    PORT
      LAYER M4 ;
        RECT  0 194.22 0.192 194.244 ;
    END
  END g_t_7_u_stin__dr_i[201]
  PIN g_t_7_u_stin__dr_i[202]
    DIRECTION INPUT ;
    USE SIGNAL ;
    PORT
      LAYER M4 ;
        RECT  0 194.604 0.192 194.628 ;
    END
  END g_t_7_u_stin__dr_i[202]
  PIN g_t_7_u_stin__dr_i[203]
    DIRECTION INPUT ;
    USE SIGNAL ;
    PORT
      LAYER M4 ;
        RECT  0 194.988 0.192 195.012 ;
    END
  END g_t_7_u_stin__dr_i[203]
  PIN g_t_7_u_stin__dr_i[204]
    DIRECTION INPUT ;
    USE SIGNAL ;
    PORT
      LAYER M4 ;
        RECT  0 195.372 0.192 195.396 ;
    END
  END g_t_7_u_stin__dr_i[204]
  PIN g_t_7_u_stin__dr_i[205]
    DIRECTION INPUT ;
    USE SIGNAL ;
    PORT
      LAYER M4 ;
        RECT  0 195.804 0.192 195.828 ;
    END
  END g_t_7_u_stin__dr_i[205]
  PIN g_t_7_u_stin__dr_i[206]
    DIRECTION INPUT ;
    USE SIGNAL ;
    PORT
      LAYER M4 ;
        RECT  0 196.188 0.192 196.212 ;
    END
  END g_t_7_u_stin__dr_i[206]
  PIN g_t_7_u_stin__dr_i[207]
    DIRECTION INPUT ;
    USE SIGNAL ;
    PORT
      LAYER M4 ;
        RECT  0 196.572 0.192 196.596 ;
    END
  END g_t_7_u_stin__dr_i[207]
  PIN g_t_7_u_stin__dr_i[208]
    DIRECTION INPUT ;
    USE SIGNAL ;
    PORT
      LAYER M4 ;
        RECT  0 197.004 0.192 197.028 ;
    END
  END g_t_7_u_stin__dr_i[208]
  PIN g_t_7_u_stin__dr_i[209]
    DIRECTION INPUT ;
    USE SIGNAL ;
    PORT
      LAYER M4 ;
        RECT  0 197.388 0.192 197.412 ;
    END
  END g_t_7_u_stin__dr_i[209]
  PIN g_t_7_u_stin__dr_i[20]
    DIRECTION INPUT ;
    USE SIGNAL ;
    PORT
      LAYER M4 ;
        RECT  0 122.46 0.192 122.484 ;
    END
  END g_t_7_u_stin__dr_i[20]
  PIN g_t_7_u_stin__dr_i[210]
    DIRECTION INPUT ;
    USE SIGNAL ;
    PORT
      LAYER M4 ;
        RECT  0 197.772 0.192 197.796 ;
    END
  END g_t_7_u_stin__dr_i[210]
  PIN g_t_7_u_stin__dr_i[211]
    DIRECTION INPUT ;
    USE SIGNAL ;
    PORT
      LAYER M4 ;
        RECT  0 198.156 0.192 198.18 ;
    END
  END g_t_7_u_stin__dr_i[211]
  PIN g_t_7_u_stin__dr_i[212]
    DIRECTION INPUT ;
    USE SIGNAL ;
    PORT
      LAYER M4 ;
        RECT  0 198.588 0.192 198.612 ;
    END
  END g_t_7_u_stin__dr_i[212]
  PIN g_t_7_u_stin__dr_i[213]
    DIRECTION INPUT ;
    USE SIGNAL ;
    PORT
      LAYER M4 ;
        RECT  0 198.972 0.192 198.996 ;
    END
  END g_t_7_u_stin__dr_i[213]
  PIN g_t_7_u_stin__dr_i[214]
    DIRECTION INPUT ;
    USE SIGNAL ;
    PORT
      LAYER M4 ;
        RECT  0 199.356 0.192 199.38 ;
    END
  END g_t_7_u_stin__dr_i[214]
  PIN g_t_7_u_stin__dr_i[215]
    DIRECTION INPUT ;
    USE SIGNAL ;
    PORT
      LAYER M4 ;
        RECT  0 199.74 0.192 199.764 ;
    END
  END g_t_7_u_stin__dr_i[215]
  PIN g_t_7_u_stin__dr_i[216]
    DIRECTION INPUT ;
    USE SIGNAL ;
    PORT
      LAYER M4 ;
        RECT  0 200.172 0.192 200.196 ;
    END
  END g_t_7_u_stin__dr_i[216]
  PIN g_t_7_u_stin__dr_i[21]
    DIRECTION INPUT ;
    USE SIGNAL ;
    PORT
      LAYER M4 ;
        RECT  0 122.844 0.192 122.868 ;
    END
  END g_t_7_u_stin__dr_i[21]
  PIN g_t_7_u_stin__dr_i[22]
    DIRECTION INPUT ;
    USE SIGNAL ;
    PORT
      LAYER M4 ;
        RECT  0 123.228 0.192 123.252 ;
    END
  END g_t_7_u_stin__dr_i[22]
  PIN g_t_7_u_stin__dr_i[23]
    DIRECTION INPUT ;
    USE SIGNAL ;
    PORT
      LAYER M4 ;
        RECT  0 123.66 0.192 123.684 ;
    END
  END g_t_7_u_stin__dr_i[23]
  PIN g_t_7_u_stin__dr_i[24]
    DIRECTION INPUT ;
    USE SIGNAL ;
    PORT
      LAYER M4 ;
        RECT  0 124.044 0.192 124.068 ;
    END
  END g_t_7_u_stin__dr_i[24]
  PIN g_t_7_u_stin__dr_i[25]
    DIRECTION INPUT ;
    USE SIGNAL ;
    PORT
      LAYER M4 ;
        RECT  0 124.428 0.192 124.452 ;
    END
  END g_t_7_u_stin__dr_i[25]
  PIN g_t_7_u_stin__dr_i[26]
    DIRECTION INPUT ;
    USE SIGNAL ;
    PORT
      LAYER M4 ;
        RECT  0 124.812 0.192 124.836 ;
    END
  END g_t_7_u_stin__dr_i[26]
  PIN g_t_7_u_stin__dr_i[27]
    DIRECTION INPUT ;
    USE SIGNAL ;
    PORT
      LAYER M4 ;
        RECT  0 125.244 0.192 125.268 ;
    END
  END g_t_7_u_stin__dr_i[27]
  PIN g_t_7_u_stin__dr_i[28]
    DIRECTION INPUT ;
    USE SIGNAL ;
    PORT
      LAYER M4 ;
        RECT  0 125.628 0.192 125.652 ;
    END
  END g_t_7_u_stin__dr_i[28]
  PIN g_t_7_u_stin__dr_i[29]
    DIRECTION INPUT ;
    USE SIGNAL ;
    PORT
      LAYER M4 ;
        RECT  0 126.012 0.192 126.036 ;
    END
  END g_t_7_u_stin__dr_i[29]
  PIN g_t_7_u_stin__dr_i[2]
    DIRECTION INPUT ;
    USE SIGNAL ;
    PORT
      LAYER M4 ;
        RECT  0 115.308 0.192 115.332 ;
    END
  END g_t_7_u_stin__dr_i[2]
  PIN g_t_7_u_stin__dr_i[30]
    DIRECTION INPUT ;
    USE SIGNAL ;
    PORT
      LAYER M4 ;
        RECT  0 126.444 0.192 126.468 ;
    END
  END g_t_7_u_stin__dr_i[30]
  PIN g_t_7_u_stin__dr_i[31]
    DIRECTION INPUT ;
    USE SIGNAL ;
    PORT
      LAYER M4 ;
        RECT  0 126.828 0.192 126.852 ;
    END
  END g_t_7_u_stin__dr_i[31]
  PIN g_t_7_u_stin__dr_i[32]
    DIRECTION INPUT ;
    USE SIGNAL ;
    PORT
      LAYER M4 ;
        RECT  0 127.212 0.192 127.236 ;
    END
  END g_t_7_u_stin__dr_i[32]
  PIN g_t_7_u_stin__dr_i[33]
    DIRECTION INPUT ;
    USE SIGNAL ;
    PORT
      LAYER M4 ;
        RECT  0 127.596 0.192 127.62 ;
    END
  END g_t_7_u_stin__dr_i[33]
  PIN g_t_7_u_stin__dr_i[34]
    DIRECTION INPUT ;
    USE SIGNAL ;
    PORT
      LAYER M4 ;
        RECT  0 128.028 0.192 128.052 ;
    END
  END g_t_7_u_stin__dr_i[34]
  PIN g_t_7_u_stin__dr_i[35]
    DIRECTION INPUT ;
    USE SIGNAL ;
    PORT
      LAYER M4 ;
        RECT  0 128.412 0.192 128.436 ;
    END
  END g_t_7_u_stin__dr_i[35]
  PIN g_t_7_u_stin__dr_i[36]
    DIRECTION INPUT ;
    USE SIGNAL ;
    PORT
      LAYER M4 ;
        RECT  0 128.796 0.192 128.82 ;
    END
  END g_t_7_u_stin__dr_i[36]
  PIN g_t_7_u_stin__dr_i[37]
    DIRECTION INPUT ;
    USE SIGNAL ;
    PORT
      LAYER M4 ;
        RECT  0 129.18 0.192 129.204 ;
    END
  END g_t_7_u_stin__dr_i[37]
  PIN g_t_7_u_stin__dr_i[38]
    DIRECTION INPUT ;
    USE SIGNAL ;
    PORT
      LAYER M4 ;
        RECT  0 129.612 0.192 129.636 ;
    END
  END g_t_7_u_stin__dr_i[38]
  PIN g_t_7_u_stin__dr_i[39]
    DIRECTION INPUT ;
    USE SIGNAL ;
    PORT
      LAYER M4 ;
        RECT  0 129.996 0.192 130.02 ;
    END
  END g_t_7_u_stin__dr_i[39]
  PIN g_t_7_u_stin__dr_i[3]
    DIRECTION INPUT ;
    USE SIGNAL ;
    PORT
      LAYER M4 ;
        RECT  0 115.74 0.192 115.764 ;
    END
  END g_t_7_u_stin__dr_i[3]
  PIN g_t_7_u_stin__dr_i[40]
    DIRECTION INPUT ;
    USE SIGNAL ;
    PORT
      LAYER M4 ;
        RECT  0 130.38 0.192 130.404 ;
    END
  END g_t_7_u_stin__dr_i[40]
  PIN g_t_7_u_stin__dr_i[41]
    DIRECTION INPUT ;
    USE SIGNAL ;
    PORT
      LAYER M4 ;
        RECT  0 130.764 0.192 130.788 ;
    END
  END g_t_7_u_stin__dr_i[41]
  PIN g_t_7_u_stin__dr_i[42]
    DIRECTION INPUT ;
    USE SIGNAL ;
    PORT
      LAYER M4 ;
        RECT  0 131.196 0.192 131.22 ;
    END
  END g_t_7_u_stin__dr_i[42]
  PIN g_t_7_u_stin__dr_i[43]
    DIRECTION INPUT ;
    USE SIGNAL ;
    PORT
      LAYER M4 ;
        RECT  0 131.58 0.192 131.604 ;
    END
  END g_t_7_u_stin__dr_i[43]
  PIN g_t_7_u_stin__dr_i[44]
    DIRECTION INPUT ;
    USE SIGNAL ;
    PORT
      LAYER M4 ;
        RECT  0 131.964 0.192 131.988 ;
    END
  END g_t_7_u_stin__dr_i[44]
  PIN g_t_7_u_stin__dr_i[45]
    DIRECTION INPUT ;
    USE SIGNAL ;
    PORT
      LAYER M4 ;
        RECT  0 132.348 0.192 132.372 ;
    END
  END g_t_7_u_stin__dr_i[45]
  PIN g_t_7_u_stin__dr_i[46]
    DIRECTION INPUT ;
    USE SIGNAL ;
    PORT
      LAYER M4 ;
        RECT  0 132.78 0.192 132.804 ;
    END
  END g_t_7_u_stin__dr_i[46]
  PIN g_t_7_u_stin__dr_i[47]
    DIRECTION INPUT ;
    USE SIGNAL ;
    PORT
      LAYER M4 ;
        RECT  0 133.164 0.192 133.188 ;
    END
  END g_t_7_u_stin__dr_i[47]
  PIN g_t_7_u_stin__dr_i[48]
    DIRECTION INPUT ;
    USE SIGNAL ;
    PORT
      LAYER M4 ;
        RECT  0 133.548 0.192 133.572 ;
    END
  END g_t_7_u_stin__dr_i[48]
  PIN g_t_7_u_stin__dr_i[49]
    DIRECTION INPUT ;
    USE SIGNAL ;
    PORT
      LAYER M4 ;
        RECT  0 133.932 0.192 133.956 ;
    END
  END g_t_7_u_stin__dr_i[49]
  PIN g_t_7_u_stin__dr_i[4]
    DIRECTION INPUT ;
    USE SIGNAL ;
    PORT
      LAYER M4 ;
        RECT  0 116.124 0.192 116.148 ;
    END
  END g_t_7_u_stin__dr_i[4]
  PIN g_t_7_u_stin__dr_i[50]
    DIRECTION INPUT ;
    USE SIGNAL ;
    PORT
      LAYER M4 ;
        RECT  0 134.364 0.192 134.388 ;
    END
  END g_t_7_u_stin__dr_i[50]
  PIN g_t_7_u_stin__dr_i[51]
    DIRECTION INPUT ;
    USE SIGNAL ;
    PORT
      LAYER M4 ;
        RECT  0 134.748 0.192 134.772 ;
    END
  END g_t_7_u_stin__dr_i[51]
  PIN g_t_7_u_stin__dr_i[52]
    DIRECTION INPUT ;
    USE SIGNAL ;
    PORT
      LAYER M4 ;
        RECT  0 135.132 0.192 135.156 ;
    END
  END g_t_7_u_stin__dr_i[52]
  PIN g_t_7_u_stin__dr_i[53]
    DIRECTION INPUT ;
    USE SIGNAL ;
    PORT
      LAYER M4 ;
        RECT  0 135.516 0.192 135.54 ;
    END
  END g_t_7_u_stin__dr_i[53]
  PIN g_t_7_u_stin__dr_i[54]
    DIRECTION INPUT ;
    USE SIGNAL ;
    PORT
      LAYER M4 ;
        RECT  0 135.948 0.192 135.972 ;
    END
  END g_t_7_u_stin__dr_i[54]
  PIN g_t_7_u_stin__dr_i[55]
    DIRECTION INPUT ;
    USE SIGNAL ;
    PORT
      LAYER M4 ;
        RECT  0 136.332 0.192 136.356 ;
    END
  END g_t_7_u_stin__dr_i[55]
  PIN g_t_7_u_stin__dr_i[56]
    DIRECTION INPUT ;
    USE SIGNAL ;
    PORT
      LAYER M4 ;
        RECT  0 136.716 0.192 136.74 ;
    END
  END g_t_7_u_stin__dr_i[56]
  PIN g_t_7_u_stin__dr_i[57]
    DIRECTION INPUT ;
    USE SIGNAL ;
    PORT
      LAYER M4 ;
        RECT  0 137.1 0.192 137.124 ;
    END
  END g_t_7_u_stin__dr_i[57]
  PIN g_t_7_u_stin__dr_i[58]
    DIRECTION INPUT ;
    USE SIGNAL ;
    PORT
      LAYER M4 ;
        RECT  0 137.532 0.192 137.556 ;
    END
  END g_t_7_u_stin__dr_i[58]
  PIN g_t_7_u_stin__dr_i[59]
    DIRECTION INPUT ;
    USE SIGNAL ;
    PORT
      LAYER M4 ;
        RECT  0 137.916 0.192 137.94 ;
    END
  END g_t_7_u_stin__dr_i[59]
  PIN g_t_7_u_stin__dr_i[5]
    DIRECTION INPUT ;
    USE SIGNAL ;
    PORT
      LAYER M4 ;
        RECT  0 116.508 0.192 116.532 ;
    END
  END g_t_7_u_stin__dr_i[5]
  PIN g_t_7_u_stin__dr_i[60]
    DIRECTION INPUT ;
    USE SIGNAL ;
    PORT
      LAYER M4 ;
        RECT  0 138.3 0.192 138.324 ;
    END
  END g_t_7_u_stin__dr_i[60]
  PIN g_t_7_u_stin__dr_i[61]
    DIRECTION INPUT ;
    USE SIGNAL ;
    PORT
      LAYER M4 ;
        RECT  0 138.732 0.192 138.756 ;
    END
  END g_t_7_u_stin__dr_i[61]
  PIN g_t_7_u_stin__dr_i[62]
    DIRECTION INPUT ;
    USE SIGNAL ;
    PORT
      LAYER M4 ;
        RECT  0 139.116 0.192 139.14 ;
    END
  END g_t_7_u_stin__dr_i[62]
  PIN g_t_7_u_stin__dr_i[63]
    DIRECTION INPUT ;
    USE SIGNAL ;
    PORT
      LAYER M4 ;
        RECT  0 139.5 0.192 139.524 ;
    END
  END g_t_7_u_stin__dr_i[63]
  PIN g_t_7_u_stin__dr_i[64]
    DIRECTION INPUT ;
    USE SIGNAL ;
    PORT
      LAYER M4 ;
        RECT  0 139.884 0.192 139.908 ;
    END
  END g_t_7_u_stin__dr_i[64]
  PIN g_t_7_u_stin__dr_i[65]
    DIRECTION INPUT ;
    USE SIGNAL ;
    PORT
      LAYER M4 ;
        RECT  0 140.316 0.192 140.34 ;
    END
  END g_t_7_u_stin__dr_i[65]
  PIN g_t_7_u_stin__dr_i[66]
    DIRECTION INPUT ;
    USE SIGNAL ;
    PORT
      LAYER M4 ;
        RECT  0 140.7 0.192 140.724 ;
    END
  END g_t_7_u_stin__dr_i[66]
  PIN g_t_7_u_stin__dr_i[67]
    DIRECTION INPUT ;
    USE SIGNAL ;
    PORT
      LAYER M4 ;
        RECT  0 141.084 0.192 141.108 ;
    END
  END g_t_7_u_stin__dr_i[67]
  PIN g_t_7_u_stin__dr_i[68]
    DIRECTION INPUT ;
    USE SIGNAL ;
    PORT
      LAYER M4 ;
        RECT  0 141.468 0.192 141.492 ;
    END
  END g_t_7_u_stin__dr_i[68]
  PIN g_t_7_u_stin__dr_i[69]
    DIRECTION INPUT ;
    USE SIGNAL ;
    PORT
      LAYER M4 ;
        RECT  0 141.9 0.192 141.924 ;
    END
  END g_t_7_u_stin__dr_i[69]
  PIN g_t_7_u_stin__dr_i[6]
    DIRECTION INPUT ;
    USE SIGNAL ;
    PORT
      LAYER M4 ;
        RECT  0 116.892 0.192 116.916 ;
    END
  END g_t_7_u_stin__dr_i[6]
  PIN g_t_7_u_stin__dr_i[70]
    DIRECTION INPUT ;
    USE SIGNAL ;
    PORT
      LAYER M4 ;
        RECT  0 142.284 0.192 142.308 ;
    END
  END g_t_7_u_stin__dr_i[70]
  PIN g_t_7_u_stin__dr_i[71]
    DIRECTION INPUT ;
    USE SIGNAL ;
    PORT
      LAYER M4 ;
        RECT  0 142.668 0.192 142.692 ;
    END
  END g_t_7_u_stin__dr_i[71]
  PIN g_t_7_u_stin__dr_i[72]
    DIRECTION INPUT ;
    USE SIGNAL ;
    PORT
      LAYER M4 ;
        RECT  0 143.052 0.192 143.076 ;
    END
  END g_t_7_u_stin__dr_i[72]
  PIN g_t_7_u_stin__dr_i[73]
    DIRECTION INPUT ;
    USE SIGNAL ;
    PORT
      LAYER M4 ;
        RECT  0 143.484 0.192 143.508 ;
    END
  END g_t_7_u_stin__dr_i[73]
  PIN g_t_7_u_stin__dr_i[74]
    DIRECTION INPUT ;
    USE SIGNAL ;
    PORT
      LAYER M4 ;
        RECT  0 143.868 0.192 143.892 ;
    END
  END g_t_7_u_stin__dr_i[74]
  PIN g_t_7_u_stin__dr_i[75]
    DIRECTION INPUT ;
    USE SIGNAL ;
    PORT
      LAYER M4 ;
        RECT  0 144.252 0.192 144.276 ;
    END
  END g_t_7_u_stin__dr_i[75]
  PIN g_t_7_u_stin__dr_i[76]
    DIRECTION INPUT ;
    USE SIGNAL ;
    PORT
      LAYER M4 ;
        RECT  0 144.636 0.192 144.66 ;
    END
  END g_t_7_u_stin__dr_i[76]
  PIN g_t_7_u_stin__dr_i[77]
    DIRECTION INPUT ;
    USE SIGNAL ;
    PORT
      LAYER M4 ;
        RECT  0 145.068 0.192 145.092 ;
    END
  END g_t_7_u_stin__dr_i[77]
  PIN g_t_7_u_stin__dr_i[78]
    DIRECTION INPUT ;
    USE SIGNAL ;
    PORT
      LAYER M4 ;
        RECT  0 145.452 0.192 145.476 ;
    END
  END g_t_7_u_stin__dr_i[78]
  PIN g_t_7_u_stin__dr_i[79]
    DIRECTION INPUT ;
    USE SIGNAL ;
    PORT
      LAYER M4 ;
        RECT  0 145.836 0.192 145.86 ;
    END
  END g_t_7_u_stin__dr_i[79]
  PIN g_t_7_u_stin__dr_i[7]
    DIRECTION INPUT ;
    USE SIGNAL ;
    PORT
      LAYER M4 ;
        RECT  0 117.324 0.192 117.348 ;
    END
  END g_t_7_u_stin__dr_i[7]
  PIN g_t_7_u_stin__dr_i[80]
    DIRECTION INPUT ;
    USE SIGNAL ;
    PORT
      LAYER M4 ;
        RECT  0 146.22 0.192 146.244 ;
    END
  END g_t_7_u_stin__dr_i[80]
  PIN g_t_7_u_stin__dr_i[81]
    DIRECTION INPUT ;
    USE SIGNAL ;
    PORT
      LAYER M4 ;
        RECT  0 146.652 0.192 146.676 ;
    END
  END g_t_7_u_stin__dr_i[81]
  PIN g_t_7_u_stin__dr_i[82]
    DIRECTION INPUT ;
    USE SIGNAL ;
    PORT
      LAYER M4 ;
        RECT  0 147.036 0.192 147.06 ;
    END
  END g_t_7_u_stin__dr_i[82]
  PIN g_t_7_u_stin__dr_i[83]
    DIRECTION INPUT ;
    USE SIGNAL ;
    PORT
      LAYER M4 ;
        RECT  0 147.42 0.192 147.444 ;
    END
  END g_t_7_u_stin__dr_i[83]
  PIN g_t_7_u_stin__dr_i[84]
    DIRECTION INPUT ;
    USE SIGNAL ;
    PORT
      LAYER M4 ;
        RECT  0 147.804 0.192 147.828 ;
    END
  END g_t_7_u_stin__dr_i[84]
  PIN g_t_7_u_stin__dr_i[85]
    DIRECTION INPUT ;
    USE SIGNAL ;
    PORT
      LAYER M4 ;
        RECT  0 148.236 0.192 148.26 ;
    END
  END g_t_7_u_stin__dr_i[85]
  PIN g_t_7_u_stin__dr_i[86]
    DIRECTION INPUT ;
    USE SIGNAL ;
    PORT
      LAYER M4 ;
        RECT  0 148.62 0.192 148.644 ;
    END
  END g_t_7_u_stin__dr_i[86]
  PIN g_t_7_u_stin__dr_i[87]
    DIRECTION INPUT ;
    USE SIGNAL ;
    PORT
      LAYER M4 ;
        RECT  0 149.004 0.192 149.028 ;
    END
  END g_t_7_u_stin__dr_i[87]
  PIN g_t_7_u_stin__dr_i[88]
    DIRECTION INPUT ;
    USE SIGNAL ;
    PORT
      LAYER M4 ;
        RECT  0 149.436 0.192 149.46 ;
    END
  END g_t_7_u_stin__dr_i[88]
  PIN g_t_7_u_stin__dr_i[89]
    DIRECTION INPUT ;
    USE SIGNAL ;
    PORT
      LAYER M4 ;
        RECT  0 149.82 0.192 149.844 ;
    END
  END g_t_7_u_stin__dr_i[89]
  PIN g_t_7_u_stin__dr_i[8]
    DIRECTION INPUT ;
    USE SIGNAL ;
    PORT
      LAYER M4 ;
        RECT  0 117.708 0.192 117.732 ;
    END
  END g_t_7_u_stin__dr_i[8]
  PIN g_t_7_u_stin__dr_i[90]
    DIRECTION INPUT ;
    USE SIGNAL ;
    PORT
      LAYER M4 ;
        RECT  0 150.204 0.192 150.228 ;
    END
  END g_t_7_u_stin__dr_i[90]
  PIN g_t_7_u_stin__dr_i[91]
    DIRECTION INPUT ;
    USE SIGNAL ;
    PORT
      LAYER M4 ;
        RECT  0 150.588 0.192 150.612 ;
    END
  END g_t_7_u_stin__dr_i[91]
  PIN g_t_7_u_stin__dr_i[92]
    DIRECTION INPUT ;
    USE SIGNAL ;
    PORT
      LAYER M4 ;
        RECT  0 151.02 0.192 151.044 ;
    END
  END g_t_7_u_stin__dr_i[92]
  PIN g_t_7_u_stin__dr_i[93]
    DIRECTION INPUT ;
    USE SIGNAL ;
    PORT
      LAYER M4 ;
        RECT  0 151.404 0.192 151.428 ;
    END
  END g_t_7_u_stin__dr_i[93]
  PIN g_t_7_u_stin__dr_i[94]
    DIRECTION INPUT ;
    USE SIGNAL ;
    PORT
      LAYER M4 ;
        RECT  0 151.788 0.192 151.812 ;
    END
  END g_t_7_u_stin__dr_i[94]
  PIN g_t_7_u_stin__dr_i[95]
    DIRECTION INPUT ;
    USE SIGNAL ;
    PORT
      LAYER M4 ;
        RECT  0 152.172 0.192 152.196 ;
    END
  END g_t_7_u_stin__dr_i[95]
  PIN g_t_7_u_stin__dr_i[96]
    DIRECTION INPUT ;
    USE SIGNAL ;
    PORT
      LAYER M4 ;
        RECT  0 152.604 0.192 152.628 ;
    END
  END g_t_7_u_stin__dr_i[96]
  PIN g_t_7_u_stin__dr_i[97]
    DIRECTION INPUT ;
    USE SIGNAL ;
    PORT
      LAYER M4 ;
        RECT  0 152.988 0.192 153.012 ;
    END
  END g_t_7_u_stin__dr_i[97]
  PIN g_t_7_u_stin__dr_i[98]
    DIRECTION INPUT ;
    USE SIGNAL ;
    PORT
      LAYER M4 ;
        RECT  0 153.372 0.192 153.396 ;
    END
  END g_t_7_u_stin__dr_i[98]
  PIN g_t_7_u_stin__dr_i[99]
    DIRECTION INPUT ;
    USE SIGNAL ;
    PORT
      LAYER M4 ;
        RECT  0 153.756 0.192 153.78 ;
    END
  END g_t_7_u_stin__dr_i[99]
  PIN g_t_7_u_stin__dr_i[9]
    DIRECTION INPUT ;
    USE SIGNAL ;
    PORT
      LAYER M4 ;
        RECT  0 118.092 0.192 118.116 ;
    END
  END g_t_7_u_stin__dr_i[9]
  PIN g_t_7_u_stin__rst_n[0]
    DIRECTION INPUT ;
    USE SIGNAL ;
    PORT
      LAYER M5 ;
        RECT  160.908 215.808 160.932 216 ;
    END
  END g_t_7_u_stin__rst_n[0]
  PIN g_t_7_u_stk__clk[0]
    DIRECTION INPUT ;
    USE SIGNAL ;
    PORT
      LAYER M5 ;
        RECT  182.076 215.808 182.1 216 ;
    END
  END g_t_7_u_stk__clk[0]
  PIN g_t_7_u_stk__gf_o[0]
    DIRECTION OUTPUT ;
    USE SIGNAL ;
    PORT
      LAYER M4 ;
        RECT  0 200.556 0.192 200.58 ;
    END
  END g_t_7_u_stk__gf_o[0]
  PIN g_t_7_u_stk__kp_o[0]
    DIRECTION OUTPUT ;
    USE SIGNAL ;
    PORT
      LAYER M4 ;
        RECT  0 200.94 0.192 200.964 ;
    END
  END g_t_7_u_stk__kp_o[0]
  PIN g_t_7_u_stk__kp_o[10]
    DIRECTION OUTPUT ;
    USE SIGNAL ;
    PORT
      LAYER M4 ;
        RECT  0 204.924 0.192 204.948 ;
    END
  END g_t_7_u_stk__kp_o[10]
  PIN g_t_7_u_stk__kp_o[11]
    DIRECTION OUTPUT ;
    USE SIGNAL ;
    PORT
      LAYER M4 ;
        RECT  0 205.308 0.192 205.332 ;
    END
  END g_t_7_u_stk__kp_o[11]
  PIN g_t_7_u_stk__kp_o[12]
    DIRECTION OUTPUT ;
    USE SIGNAL ;
    PORT
      LAYER M4 ;
        RECT  0 205.692 0.192 205.716 ;
    END
  END g_t_7_u_stk__kp_o[12]
  PIN g_t_7_u_stk__kp_o[13]
    DIRECTION OUTPUT ;
    USE SIGNAL ;
    PORT
      LAYER M4 ;
        RECT  0 206.076 0.192 206.1 ;
    END
  END g_t_7_u_stk__kp_o[13]
  PIN g_t_7_u_stk__kp_o[14]
    DIRECTION OUTPUT ;
    USE SIGNAL ;
    PORT
      LAYER M4 ;
        RECT  0 206.508 0.192 206.532 ;
    END
  END g_t_7_u_stk__kp_o[14]
  PIN g_t_7_u_stk__kp_o[15]
    DIRECTION OUTPUT ;
    USE SIGNAL ;
    PORT
      LAYER M4 ;
        RECT  0 206.892 0.192 206.916 ;
    END
  END g_t_7_u_stk__kp_o[15]
  PIN g_t_7_u_stk__kp_o[16]
    DIRECTION OUTPUT ;
    USE SIGNAL ;
    PORT
      LAYER M4 ;
        RECT  0 207.276 0.192 207.3 ;
    END
  END g_t_7_u_stk__kp_o[16]
  PIN g_t_7_u_stk__kp_o[17]
    DIRECTION OUTPUT ;
    USE SIGNAL ;
    PORT
      LAYER M4 ;
        RECT  0 207.66 0.192 207.684 ;
    END
  END g_t_7_u_stk__kp_o[17]
  PIN g_t_7_u_stk__kp_o[18]
    DIRECTION OUTPUT ;
    USE SIGNAL ;
    PORT
      LAYER M4 ;
        RECT  0 208.092 0.192 208.116 ;
    END
  END g_t_7_u_stk__kp_o[18]
  PIN g_t_7_u_stk__kp_o[19]
    DIRECTION OUTPUT ;
    USE SIGNAL ;
    PORT
      LAYER M4 ;
        RECT  0 208.476 0.192 208.5 ;
    END
  END g_t_7_u_stk__kp_o[19]
  PIN g_t_7_u_stk__kp_o[1]
    DIRECTION OUTPUT ;
    USE SIGNAL ;
    PORT
      LAYER M4 ;
        RECT  0 201.324 0.192 201.348 ;
    END
  END g_t_7_u_stk__kp_o[1]
  PIN g_t_7_u_stk__kp_o[20]
    DIRECTION OUTPUT ;
    USE SIGNAL ;
    PORT
      LAYER M4 ;
        RECT  0 208.86 0.192 208.884 ;
    END
  END g_t_7_u_stk__kp_o[20]
  PIN g_t_7_u_stk__kp_o[21]
    DIRECTION OUTPUT ;
    USE SIGNAL ;
    PORT
      LAYER M4 ;
        RECT  0 209.292 0.192 209.316 ;
    END
  END g_t_7_u_stk__kp_o[21]
  PIN g_t_7_u_stk__kp_o[22]
    DIRECTION OUTPUT ;
    USE SIGNAL ;
    PORT
      LAYER M4 ;
        RECT  0 209.676 0.192 209.7 ;
    END
  END g_t_7_u_stk__kp_o[22]
  PIN g_t_7_u_stk__kp_o[23]
    DIRECTION OUTPUT ;
    USE SIGNAL ;
    PORT
      LAYER M4 ;
        RECT  0 210.06 0.192 210.084 ;
    END
  END g_t_7_u_stk__kp_o[23]
  PIN g_t_7_u_stk__kp_o[24]
    DIRECTION OUTPUT ;
    USE SIGNAL ;
    PORT
      LAYER M4 ;
        RECT  0 210.444 0.192 210.468 ;
    END
  END g_t_7_u_stk__kp_o[24]
  PIN g_t_7_u_stk__kp_o[25]
    DIRECTION OUTPUT ;
    USE SIGNAL ;
    PORT
      LAYER M4 ;
        RECT  0 210.876 0.192 210.9 ;
    END
  END g_t_7_u_stk__kp_o[25]
  PIN g_t_7_u_stk__kp_o[26]
    DIRECTION OUTPUT ;
    USE SIGNAL ;
    PORT
      LAYER M4 ;
        RECT  0 211.26 0.192 211.284 ;
    END
  END g_t_7_u_stk__kp_o[26]
  PIN g_t_7_u_stk__kp_o[27]
    DIRECTION OUTPUT ;
    USE SIGNAL ;
    PORT
      LAYER M4 ;
        RECT  0 211.644 0.192 211.668 ;
    END
  END g_t_7_u_stk__kp_o[27]
  PIN g_t_7_u_stk__kp_o[28]
    DIRECTION OUTPUT ;
    USE SIGNAL ;
    PORT
      LAYER M4 ;
        RECT  0 212.028 0.192 212.052 ;
    END
  END g_t_7_u_stk__kp_o[28]
  PIN g_t_7_u_stk__kp_o[29]
    DIRECTION OUTPUT ;
    USE SIGNAL ;
    PORT
      LAYER M4 ;
        RECT  0 212.46 0.192 212.484 ;
    END
  END g_t_7_u_stk__kp_o[29]
  PIN g_t_7_u_stk__kp_o[2]
    DIRECTION OUTPUT ;
    USE SIGNAL ;
    PORT
      LAYER M4 ;
        RECT  0 201.756 0.192 201.78 ;
    END
  END g_t_7_u_stk__kp_o[2]
  PIN g_t_7_u_stk__kp_o[30]
    DIRECTION OUTPUT ;
    USE SIGNAL ;
    PORT
      LAYER M4 ;
        RECT  0 212.844 0.192 212.868 ;
    END
  END g_t_7_u_stk__kp_o[30]
  PIN g_t_7_u_stk__kp_o[31]
    DIRECTION OUTPUT ;
    USE SIGNAL ;
    PORT
      LAYER M4 ;
        RECT  0 213.228 0.192 213.252 ;
    END
  END g_t_7_u_stk__kp_o[31]
  PIN g_t_7_u_stk__kp_o[3]
    DIRECTION OUTPUT ;
    USE SIGNAL ;
    PORT
      LAYER M4 ;
        RECT  0 202.14 0.192 202.164 ;
    END
  END g_t_7_u_stk__kp_o[3]
  PIN g_t_7_u_stk__kp_o[4]
    DIRECTION OUTPUT ;
    USE SIGNAL ;
    PORT
      LAYER M4 ;
        RECT  0 202.524 0.192 202.548 ;
    END
  END g_t_7_u_stk__kp_o[4]
  PIN g_t_7_u_stk__kp_o[5]
    DIRECTION OUTPUT ;
    USE SIGNAL ;
    PORT
      LAYER M4 ;
        RECT  0 202.908 0.192 202.932 ;
    END
  END g_t_7_u_stk__kp_o[5]
  PIN g_t_7_u_stk__kp_o[6]
    DIRECTION OUTPUT ;
    USE SIGNAL ;
    PORT
      LAYER M4 ;
        RECT  0 203.34 0.192 203.364 ;
    END
  END g_t_7_u_stk__kp_o[6]
  PIN g_t_7_u_stk__kp_o[7]
    DIRECTION OUTPUT ;
    USE SIGNAL ;
    PORT
      LAYER M4 ;
        RECT  0 203.724 0.192 203.748 ;
    END
  END g_t_7_u_stk__kp_o[7]
  PIN g_t_7_u_stk__kp_o[8]
    DIRECTION OUTPUT ;
    USE SIGNAL ;
    PORT
      LAYER M4 ;
        RECT  0 204.108 0.192 204.132 ;
    END
  END g_t_7_u_stk__kp_o[8]
  PIN g_t_7_u_stk__kp_o[9]
    DIRECTION OUTPUT ;
    USE SIGNAL ;
    PORT
      LAYER M4 ;
        RECT  0 204.492 0.192 204.516 ;
    END
  END g_t_7_u_stk__kp_o[9]
  PIN g_t_7_u_stk__kpv_o[0]
    DIRECTION OUTPUT ;
    USE SIGNAL ;
    PORT
      LAYER M4 ;
        RECT  0 213.612 0.192 213.636 ;
    END
  END g_t_7_u_stk__kpv_o[0]
  PIN g_t_7_u_stk__rst_n[0]
    DIRECTION INPUT ;
    USE SIGNAL ;
    PORT
      LAYER M5 ;
        RECT  203.244 215.808 203.268 216 ;
    END
  END g_t_7_u_stk__rst_n[0]
  PIN VSS
    DIRECTION INOUT ;
    USE GROUND ;
    PORT
      LAYER M5 ;
        RECT  209.364 4.297 209.484 211.703 ;
        RECT  205.044 4.297 205.164 211.703 ;
        RECT  200.724 4.297 200.844 211.703 ;
        RECT  196.404 4.297 196.524 211.703 ;
        RECT  192.084 4.297 192.204 211.703 ;
        RECT  187.764 4.297 187.884 211.703 ;
        RECT  183.444 4.297 183.564 211.703 ;
        RECT  179.124 4.297 179.244 211.703 ;
        RECT  174.804 4.297 174.924 211.703 ;
        RECT  170.484 4.297 170.604 211.703 ;
        RECT  166.164 4.297 166.284 211.703 ;
        RECT  161.844 4.297 161.964 211.703 ;
        RECT  157.524 4.297 157.644 211.703 ;
        RECT  153.204 4.297 153.324 211.703 ;
        RECT  148.884 4.297 149.004 211.703 ;
        RECT  144.564 4.297 144.684 211.703 ;
        RECT  140.244 4.297 140.364 211.703 ;
        RECT  135.924 4.297 136.044 211.703 ;
        RECT  131.604 4.297 131.724 211.703 ;
        RECT  127.284 4.297 127.404 211.703 ;
        RECT  122.964 4.297 123.084 211.703 ;
        RECT  118.644 4.297 118.764 211.703 ;
        RECT  114.324 4.297 114.444 211.703 ;
        RECT  110.004 4.297 110.124 211.703 ;
        RECT  105.684 4.297 105.804 211.703 ;
        RECT  101.364 4.297 101.484 211.703 ;
        RECT  97.044 4.297 97.164 211.703 ;
        RECT  92.724 4.297 92.844 211.703 ;
        RECT  88.404 4.297 88.524 211.703 ;
        RECT  84.084 4.297 84.204 211.703 ;
        RECT  79.764 4.297 79.884 211.703 ;
        RECT  75.444 4.297 75.564 211.703 ;
        RECT  71.124 4.297 71.244 211.703 ;
        RECT  66.804 4.297 66.924 211.703 ;
        RECT  62.484 4.297 62.604 211.703 ;
        RECT  58.164 4.297 58.284 211.703 ;
        RECT  53.844 4.297 53.964 211.703 ;
        RECT  49.524 4.297 49.644 211.703 ;
        RECT  45.204 4.297 45.324 211.703 ;
        RECT  40.884 4.297 41.004 211.703 ;
        RECT  36.564 4.297 36.684 211.703 ;
        RECT  32.244 4.297 32.364 211.703 ;
        RECT  27.924 4.297 28.044 211.703 ;
        RECT  23.604 4.297 23.724 211.703 ;
        RECT  19.284 4.297 19.404 211.703 ;
        RECT  14.964 4.297 15.084 211.703 ;
        RECT  10.644 4.297 10.764 211.703 ;
        RECT  6.324 4.297 6.444 211.703 ;
    END
  END VSS
  PIN VDD
    DIRECTION INOUT ;
    USE POWER ;
    PORT
      LAYER M5 ;
        RECT  209.556 4.311 209.676 211.689 ;
        RECT  205.236 4.311 205.356 211.689 ;
        RECT  200.916 4.311 201.036 211.689 ;
        RECT  196.596 4.311 196.716 211.689 ;
        RECT  192.276 4.311 192.396 211.689 ;
        RECT  187.956 4.311 188.076 211.689 ;
        RECT  183.636 4.311 183.756 211.689 ;
        RECT  179.316 4.311 179.436 211.689 ;
        RECT  174.996 4.311 175.116 211.689 ;
        RECT  170.676 4.311 170.796 211.689 ;
        RECT  166.356 4.311 166.476 211.689 ;
        RECT  162.036 4.311 162.156 211.689 ;
        RECT  157.716 4.311 157.836 211.689 ;
        RECT  153.396 4.311 153.516 211.689 ;
        RECT  149.076 4.311 149.196 211.689 ;
        RECT  144.756 4.311 144.876 211.689 ;
        RECT  140.436 4.311 140.556 211.689 ;
        RECT  136.116 4.311 136.236 211.689 ;
        RECT  131.796 4.311 131.916 211.689 ;
        RECT  127.476 4.311 127.596 211.689 ;
        RECT  123.156 4.311 123.276 211.689 ;
        RECT  118.836 4.311 118.956 211.689 ;
        RECT  114.516 4.311 114.636 211.689 ;
        RECT  110.196 4.311 110.316 211.689 ;
        RECT  105.876 4.311 105.996 211.689 ;
        RECT  101.556 4.311 101.676 211.689 ;
        RECT  97.236 4.311 97.356 211.689 ;
        RECT  92.916 4.311 93.036 211.689 ;
        RECT  88.596 4.311 88.716 211.689 ;
        RECT  84.276 4.311 84.396 211.689 ;
        RECT  79.956 4.311 80.076 211.689 ;
        RECT  75.636 4.311 75.756 211.689 ;
        RECT  71.316 4.311 71.436 211.689 ;
        RECT  66.996 4.311 67.116 211.689 ;
        RECT  62.676 4.311 62.796 211.689 ;
        RECT  58.356 4.311 58.476 211.689 ;
        RECT  54.036 4.311 54.156 211.689 ;
        RECT  49.716 4.311 49.836 211.689 ;
        RECT  45.396 4.311 45.516 211.689 ;
        RECT  41.076 4.311 41.196 211.689 ;
        RECT  36.756 4.311 36.876 211.689 ;
        RECT  32.436 4.311 32.556 211.689 ;
        RECT  28.116 4.311 28.236 211.689 ;
        RECT  23.796 4.311 23.916 211.689 ;
        RECT  19.476 4.311 19.596 211.689 ;
        RECT  15.156 4.311 15.276 211.689 ;
        RECT  10.836 4.311 10.956 211.689 ;
        RECT  6.516 4.311 6.636 211.689 ;
    END
  END VDD
  OBS
    LAYER RVTN ;
     RECT  0 2.359 211.68 216 ;
    LAYER RVTP ;
     RECT  0 2.359 211.68 216 ;
    LAYER M1 ;
     RECT  0 2.359 211.68 216 ;
    LAYER M2 ;
     RECT  0 2.359 211.68 216 ;
    LAYER M3 ;
     RECT  0 2.359 211.68 216 ;
    LAYER M4 ;
     RECT  0 2.359 211.68 216 ;
    LAYER M5 ;
     RECT  0 2.359 211.68 216 ;
    LAYER M6 ;
     RECT  0 2.359 211.68 216 ;
    LAYER M7 ;
     RECT  0 2.359 211.68 216 ;
  END
END kv3_head_eighth_e3
END LIBRARY
